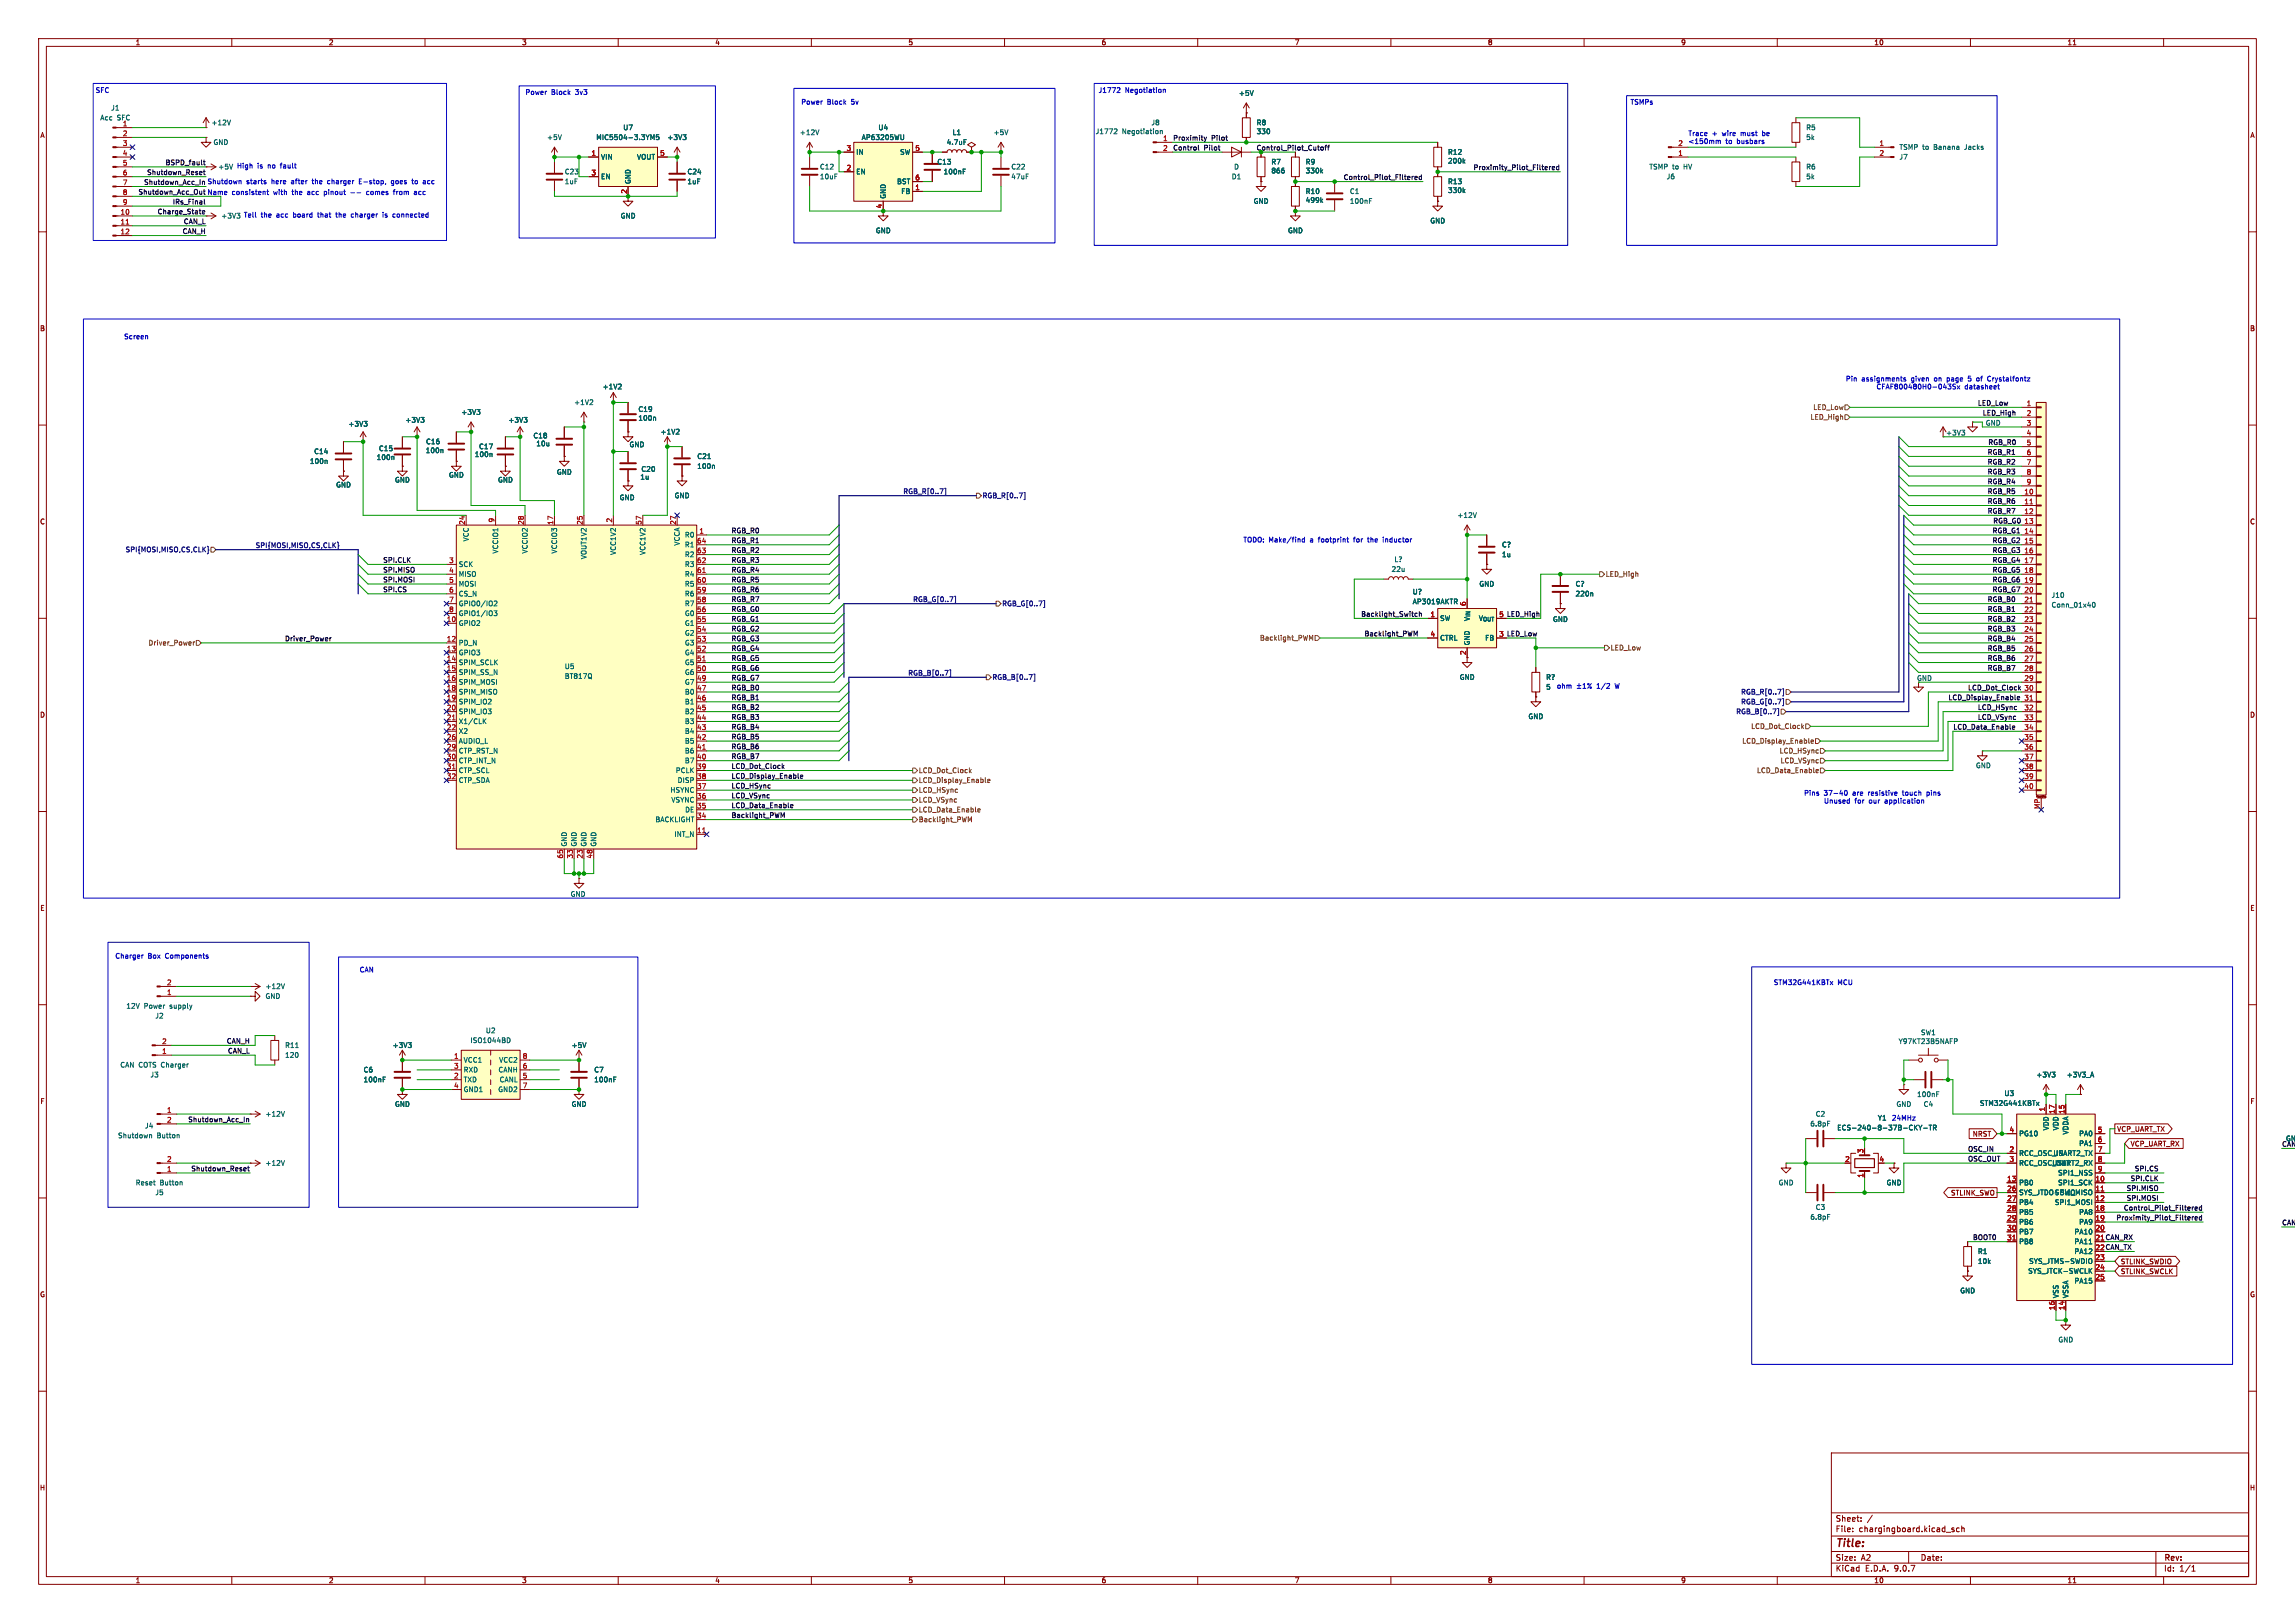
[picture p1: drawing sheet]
<svg xmlns="http://www.w3.org/2000/svg" width="594mm" height="420mm" viewBox="0 0 594 420" stroke-linecap="round" stroke-linejoin="round" font-family="sans-serif">
<defs><g id="words">
<text font-size="2.8" fill="#840000" x="475" y="400.9">Title:</text>
<g font-size="2.1" fill="#840000">
<text x="475" y="394">Sheet:</text>
<text x="475" y="396.7">File:</text>
<text x="481.1" y="396.7">chargingboard.kicad_sch</text>
<text x="475" y="406.9">KiCad</text>
<text x="475" y="404.1">Size:</text>
<text x="481.7" y="404.1">A2</text>
<text x="482.7" y="406.9">E.D.A.</text>
<text x="490.3" y="406.9">9.0.7</text>
<text x="497" y="404.1">Date:</text>
<text x="560" y="404.3">Rev:</text>
<text x="560" y="406.9">Id:</text>
<text x="564.1" y="406.9">1/1</text>
</g>
<g font-size="1.8" fill="#840000">
<text x="35" y="11.9">1</text>
<text x="85" y="11.9">2</text>
<text x="135" y="11.9">3</text>
<text x="185" y="11.9">4</text>
<text x="235" y="11.9">5</text>
<text x="285" y="11.9">6</text>
<text x="335" y="11.9">7</text>
<text x="385" y="11.9">8</text>
<text x="435" y="11.9">9</text>
<text x="485" y="11.9">10</text>
<text x="535" y="11.9">11</text>
<text x="10.3" y="35.9">A</text>
<text x="582.3" y="35.9">A</text>
<text x="228.3" y="54" transform="rotate(-90 228.3 54)">4</text>
<text x="10.3" y="85.9">B</text>
<text x="582.3" y="85.9">B</text>
<text x="10.3" y="135.9">C</text>
<text x="582.3" y="135.9">C</text>
<text x="10.3" y="185.9">D</text>
<text x="582.3" y="185.9">D</text>
<text x="10.3" y="235.9">E</text>
<text x="582.3" y="235.9">E</text>
<text x="10.3" y="285.9">F</text>
<text x="582.3" y="285.9">F</text>
<text x="547.8" y="293.1">VCP_UART_TX</text>
<text x="510.5" y="294.3">NRST</text>
<text x="551.3" y="296.9">VCP_UART_RX</text>
<text x="504.8" y="309.6">STLINK_SWO</text>
<text x="542.2" y="323.6">22 CAN_TX</text>
<text x="548.8" y="329.9">STLINK_SWCLK</text>
<text x="548.8" y="327.3">STLINK_SWDIO</text>
<text x="10.3" y="335.9">G</text>
<text x="582.3" y="335.9">G</text>
<text x="10.2" y="385.9">H</text>
<text x="582.2" y="385.9">H</text>
<text x="35" y="409.9">1</text>
<text x="85" y="409.9">2</text>
<text x="135" y="409.9">3</text>
<text x="185" y="409.9">4</text>
<text x="235" y="409.9">5</text>
<text x="285" y="409.9">6</text>
<text x="335" y="409.9">7</text>
<text x="385" y="409.9">8</text>
<text x="435" y="409.9">9</text>
<text x="485" y="409.9">10</text>
<text x="535" y="409.9">11</text>
</g>
<g font-size="1.8" fill="#0000c2">
<text x="24.6" y="24.2">SFC</text>
<text x="135.9" y="24.7">Power</text>
<text x="142.7" y="24.7">Block</text>
<text x="149.1" y="24.7">3v3</text>
<text x="207.3" y="27.3">Power</text>
<text x="214.1" y="27.3">Block</text>
<text x="220.4" y="27.3">5v</text>
<text x="284.2" y="24.2">J1772</text>
<text x="291.2" y="24.2">Negotiation</text>
<text x="421.9" y="27.3">TSMPs</text>
<text x="436.9" y="35.4">Trace</text>
<text x="443.1" y="35.4">+</text>
<text x="445.9" y="35.4">wire</text>
<text x="450.9" y="35.4">must</text>
<text x="456.6" y="35.4">be</text>
<text x="436.9" y="37.4">&lt;150mm</text>
<text x="446.6" y="37.4">to</text>
<text x="449.7" y="37.4">busbars</text>
<text x="53.6" y="47.9">Shutdown</text>
<text x="61.2" y="43.8">High</text>
<text x="63.8" y="47.9">starts</text>
<text x="66.6" y="43.8">is</text>
<text x="69.4" y="43.8">no</text>
<text x="70.4" y="47.9">here</text>
<text x="72.9" y="43.8">fault</text>
<text x="75.7" y="47.9">after</text>
<text x="81.3" y="47.9">the</text>
<text x="85.5" y="47.9">charger</text>
<text x="93.8" y="47.9">E-stop,</text>
<text x="102.4" y="47.9">goes</text>
<text x="108" y="47.9">to</text>
<text x="111" y="47.9">acc</text>
<text x="53.6" y="50.7">Name</text>
<text x="60" y="50.7">consistent</text>
<text x="70.9" y="50.7">with</text>
<text x="75.9" y="50.7">the</text>
<text x="80" y="50.7">acc</text>
<text x="84.5" y="50.7">pinout</text>
<text x="96" y="50.7">comes</text>
<text x="103.2" y="50.7">from</text>
<text x="108.7" y="50.7">acc</text>
<text x="63" y="56.5">Tell</text>
<text x="67.5" y="56.5">the</text>
<text x="71.7" y="56.5">acc</text>
<text x="76.2" y="56.5">board</text>
<text x="82.7" y="56.5">that</text>
<text x="87.7" y="56.5">the</text>
<text x="91.8" y="56.5">charger</text>
<text x="100.2" y="56.5">is</text>
<text x="103" y="56.5">connected</text>
<text x="32" y="88">Screen</text>
<text x="477.6" y="98.9">Pin</text>
<text x="481.8" y="98.9">assignments</text>
<text x="485.6" y="100.9">CFAF800480H0-043Sx</text>
<text x="494.8" y="98.9">given</text>
<text x="500.9" y="98.9">on</text>
<text x="504.4" y="98.9">page</text>
<text x="508.5" y="100.9">datasheet</text>
<text x="510.1" y="98.9">5</text>
<text x="512.5" y="98.9">of</text>
<text x="515.5" y="98.9">Crystalfontz</text>
<text x="321.7" y="140.6">TODO: Make/find</text>
<text x="339.2" y="140.6">a</text>
<text x="341.5" y="140.6">footprint</text>
<text x="350.9" y="140.6">for</text>
<text x="354.7" y="140.6">the</text>
<text x="358.8" y="140.6">inductor</text>
<text x="402.8" y="178.4">ohm</text>
<text x="413.4" y="178.4">1/2</text>
<text x="418.3" y="178.4">W</text>
<text x="466.8" y="206.1">Pins</text>
<text x="472" y="208.1">Unused</text>
<text x="472.1" y="206.1">37-40</text>
<text x="479.6" y="206.1">are</text>
<text x="480" y="208.1">for</text>
<text x="483.8" y="206.1">resistive</text>
<text x="483.9" y="208.1">our</text>
<text x="488.1" y="208.1">application</text>
<text x="492.9" y="206.1">touch</text>
<text x="499.4" y="206.1">pins</text>
<text x="29.7" y="248.3">Charger</text>
<text x="38.3" y="248.3">Box</text>
<text x="42.9" y="248.3">Components</text>
<text x="93" y="251.8">CAN</text>
<text x="459" y="255.2">STM32G441KBTx</text>
<text x="475.6" y="255.2">MCU</text>
<text x="489.5" y="290.2">24MHz</text>
</g>
<g font-size="1.8" fill="#006464">
<text x="28.7" y="28.8">J1</text>
<text x="320.5" y="25">+5V</text>
<text x="25.8" y="31.3">Acc</text>
<text x="30.3" y="31.3">SFC</text>
<text x="54.6" y="32.6">+12V</text>
<text x="161.2" y="33.9">U7</text>
<text x="206.9" y="35.2">+12V</text>
<text x="227.2" y="33.9">U4</text>
<text x="246.4" y="35.2">L1</text>
<text x="257" y="35.2">+5V</text>
<text x="283.5" y="34.9">J1772</text>
<text x="290.4" y="34.9">Negotiation</text>
<text x="297.9" y="32.6">J8</text>
<text x="325.1" y="32.6">R8</text>
<text x="325.1" y="34.9">330</text>
<text x="467.4" y="33.9">R5</text>
<text x="55.1" y="37.7">GND</text>
<text x="141.5" y="36.4">+5V</text>
<text x="154.2" y="36.4">MIC5504-3.3YM5</text>
<text x="155.4" y="41.5">VIN</text>
<text x="164.8" y="41.5">VOUT</text>
<text x="172.6" y="36.4">+3V3</text>
<text x="221.5" y="40.2">IN</text>
<text x="222.9" y="36.4">AP63205WU</text>
<text x="232.8" y="40.2">SW</text>
<text x="244.9" y="37.7">4.7uF</text>
<text x="374.7" y="40.2">R12</text>
<text x="467.4" y="36.4">5k</text>
<text x="491.5" y="41.5">J7</text>
<text x="491.5" y="39">TSMP to</text>
<text x="500.6" y="39">Banana</text>
<text x="508.8" y="39">Jacks</text>
<text x="56.4" y="44">+5V</text>
<text x="146.1" y="47.9">1uF</text>
<text x="146.1" y="45.3">C23</text>
<text x="155.4" y="46.6">EN</text>
<text x="163.4" y="47.8" transform="rotate(-90 163.4 47.8)">GND</text>
<text x="177.8" y="47.9">1uF</text>
<text x="177.8" y="45.3">C24</text>
<text x="212.1" y="44">C12</text>
<text x="212.1" y="46.6">10uF</text>
<text x="221.5" y="45.3">EN</text>
<text x="232.1" y="47.9">BST</text>
<text x="242.5" y="42.8">C13</text>
<text x="244.1" y="45.3">100nF</text>
<text x="261.6" y="44">C22</text>
<text x="261.6" y="46.6">47uF</text>
<text x="318.7" y="46.6">D1</text>
<text x="319.3" y="44">D</text>
<text x="328.9" y="42.8">R7</text>
<text x="328.9" y="45.1">866</text>
<text x="337.8" y="42.8">R9</text>
<text x="337.8" y="45.1">330k</text>
<text x="374.7" y="47.9">R13</text>
<text x="374.7" y="42.5">200k</text>
<text x="426.8" y="44">TSMP to</text>
<text x="431.2" y="46.6">J6</text>
<text x="435.9" y="44">HV</text>
<text x="467.4" y="44">R6</text>
<text x="467.4" y="46.6">5k</text>
<text x="229.5" y="51.6" transform="rotate(-90 229.5 51.6)">GND</text>
<text x="233.2" y="50.4">FB</text>
<text x="324.4" y="52.9">GND</text>
<text x="337.8" y="50.4">R10</text>
<text x="337.8" y="52.7">499k</text>
<text x="349.3" y="50.4">C1</text>
<text x="349.3" y="52.9">100nF</text>
<text x="374.7" y="50.1">330k</text>
<text x="57.2" y="56.7">+3V3</text>
<text x="160.5" y="56.7">GND</text>
<text x="370.1" y="58">GND</text>
<text x="226.6" y="60.6">GND</text>
<text x="333.2" y="60.6">GND</text>
<text x="155.9" y="100.9">+1V2</text>
<text x="119.3" y="107.5">+3V3</text>
<text x="148.5" y="105">+1V2</text>
<text x="165.1" y="106.8">C19</text>
<text x="90.1" y="110.6">+3V3</text>
<text x="104.8" y="109.6">+3V3</text>
<text x="131.5" y="109.6">+3V3</text>
<text x="137.9" y="113.6">C18</text>
<text x="165.1" y="109.1">100n</text>
<text x="170.8" y="112.6">+1V2</text>
<text x="503.6" y="112.9">+3V3</text>
<text x="513.8" y="110.3">GND</text>
<text x="81.2" y="117.7">C14</text>
<text x="97.4" y="119.2">100n</text>
<text x="98" y="116.9">C15</text>
<text x="110.1" y="117.4">100n</text>
<text x="110.1" y="115.2">C16</text>
<text x="122.8" y="118.5">100n</text>
<text x="123.9" y="116.4">C17</text>
<text x="138.7" y="115.7">10u</text>
<text x="162.8" y="115.9">GND</text>
<text x="180.3" y="119">C21</text>
<text x="80.1" y="120.2">100n</text>
<text x="102.1" y="125.1">GND</text>
<text x="116.1" y="123.8">GND</text>
<text x="128.8" y="125.1">GND</text>
<text x="144" y="123">GND</text>
<text x="165.6" y="124.3">1u</text>
<text x="165.9" y="122.3">C20</text>
<text x="180.3" y="121.5">100n</text>
<text x="86.9" y="126.3">GND</text>
<text x="160.3" y="129.6">GND</text>
<text x="174.5" y="129.1">GND</text>
<text x="377.1" y="134.2">+12V</text>
<text x="121.5" y="140.2" transform="rotate(-90 121.5 140.2)">VCC</text>
<text x="129.1" y="143.4" transform="rotate(-90 129.1 143.4)">VCCIO1</text>
<text x="136.8" y="143.4" transform="rotate(-90 136.8 143.4)">VCCIO2</text>
<text x="144.4" y="143.4" transform="rotate(-90 144.4 143.4)">VCCIO3</text>
<text x="159.6" y="143.7" transform="rotate(-90 159.6 143.7)">VCC1V2</text>
<text x="167.2" y="143.7" transform="rotate(-90 167.2 143.7)">VCC1V2</text>
<text x="176.1" y="141.3" transform="rotate(-90 176.1 141.3)">VCCA</text>
<text x="177.1" y="139.3">R0</text>
<text x="177.1" y="141.8">R1</text>
<text x="388.6" y="141.8">C?</text>
<text x="118.6" y="146.9">SCK</text>
<text x="118.6" y="149.5">MISO</text>
<text x="152" y="144.8" transform="rotate(-90 152 144.8)">VOUT1V2</text>
<text x="177.1" y="144.4">R2</text>
<text x="177.1" y="146.9">R3</text>
<text x="177.1" y="149.5">R4</text>
<text x="360.1" y="148.2">22u</text>
<text x="360.8" y="145.6">L?</text>
<text x="388.6" y="144.4">1u</text>
<text x="118.6" y="152">MOSI</text>
<text x="118.6" y="154.5">CS_N</text>
<text x="177.1" y="152">R5</text>
<text x="177.1" y="154.5">R6</text>
<text x="365.5" y="154">U?</text>
<text x="382.8" y="152">GND</text>
<text x="407.7" y="154.5">220n</text>
<text x="407.7" y="152">C?</text>
<text x="530.9" y="154.9">J10</text>
<text x="118.6" y="157.1">GPIO0/IO2</text>
<text x="118.6" y="159.6">GPIO1/IO3</text>
<text x="177.1" y="157.1">R7</text>
<text x="177.1" y="159.6">G0</text>
<text x="365.5" y="156.6">AP3019AKTR</text>
<text x="372.6" y="160.9">SW</text>
<text x="380.6" y="160.9" transform="rotate(-90 380.6 160.9)">V_{IN}</text>
<text x="382.6" y="160.9">V_{OUT}</text>
<text x="401.8" y="161.1">GND</text>
<text x="530.9" y="157.4">Conn_01x40</text>
<text x="118.6" y="162.2">GPIO2</text>
<text x="118.6" y="167.2">PD_N</text>
<text x="177.1" y="162.2">G1</text>
<text x="177.1" y="164.7">G2</text>
<text x="177.1" y="167.2">G3</text>
<text x="372.6" y="166">CTRL</text>
<text x="380.6" y="167.1" transform="rotate(-90 380.6 167.1)">GND</text>
<text x="384.3" y="166">FB</text>
<text x="118.6" y="169.8">GPIO3</text>
<text x="118.6" y="172.3">SPIM_SCLK</text>
<text x="146.1" y="173.3">U5</text>
<text x="177.1" y="169.8">G4</text>
<text x="177.1" y="172.3">G5</text>
<text x="118.6" y="174.9">SPIM_SS_N</text>
<text x="118.6" y="177.4">SPIM_MOSI</text>
<text x="118.6" y="179.9">SPIM_MISO</text>
<text x="146.1" y="175.9">BT817Q</text>
<text x="177.1" y="174.9">G6</text>
<text x="177.1" y="177.4">G7</text>
<text x="177.1" y="179.9">B0</text>
<text x="377.7" y="176.1">GND</text>
<text x="400.1" y="178.7">5</text>
<text x="400.1" y="176.1">R?</text>
<text x="496.1" y="176.4">GND</text>
<text x="118.6" y="182.5">SPIM_IO2</text>
<text x="118.6" y="185">SPIM_IO3</text>
<text x="177.1" y="182.5">B1</text>
<text x="177.1" y="185">B2</text>
<text x="118.6" y="187.6">X1/CLK</text>
<text x="118.6" y="190.1">X2</text>
<text x="177.1" y="187.6">B3</text>
<text x="177.1" y="190.1">B4</text>
<text x="395.5" y="186.3">GND</text>
<text x="118.6" y="192.6">AUDIO_L</text>
<text x="118.6" y="195.2">CTP_RST_N</text>
<text x="118.6" y="197.7">CTP_INT_N</text>
<text x="177.1" y="192.6">B5</text>
<text x="177.1" y="195.2">B6</text>
<text x="177.1" y="197.7">B7</text>
<text x="118.6" y="200.3">CTP_SCL</text>
<text x="118.6" y="202.8">CTP_SDA</text>
<text x="174.8" y="200.3">PCLK</text>
<text x="175.3" y="202.8">DISP</text>
<text x="511.3" y="199">GND</text>
<text x="173.4" y="205.3">HSYNC</text>
<text x="173.6" y="207.9">VSYNC</text>
<text x="169.5" y="213">BACKLIGHT</text>
<text x="177.2" y="210.4">DE</text>
<text x="146.9" y="219.2" transform="rotate(-90 146.9 219.2)">GND</text>
<text x="149.5" y="219.2" transform="rotate(-90 149.5 219.2)">GND</text>
<text x="152" y="219.2" transform="rotate(-90 152 219.2)">GND</text>
<text x="154.5" y="219.2" transform="rotate(-90 154.5 219.2)">GND</text>
<text x="174.4" y="216.8">INT_N</text>
<text x="147.6" y="232.3">GND</text>
<text x="68.6" y="256.1">+12V</text>
<text x="32.6" y="261.2">12V</text>
<text x="37.3" y="261.2">Power</text>
<text x="40.1" y="263.8">J2</text>
<text x="44.1" y="261.2">supply</text>
<text x="68.6" y="258.7">GND</text>
<text x="125.6" y="267.6">U2</text>
<text x="497.1" y="268.1">SW1</text>
<text x="73.7" y="273.9">120</text>
<text x="73.7" y="271.4">R11</text>
<text x="101.5" y="271.4">+3V3</text>
<text x="119.9" y="275.2">VCC1</text>
<text x="121.6" y="270.1">ISO1044BD</text>
<text x="129.1" y="275.2">VCC2</text>
<text x="147.8" y="271.4">+5V</text>
<text x="491.3" y="270.4">Y97KT23B5NAFP</text>
<text x="31" y="276.5">CAN COTS Charger</text>
<text x="38.8" y="279">J3</text>
<text x="94" y="277.7">C6</text>
<text x="94" y="280.3">100nF</text>
<text x="119.9" y="277.7">RXD</text>
<text x="119.9" y="280.3">TXD</text>
<text x="128.9" y="277.7">CANH</text>
<text x="129.2" y="280.3">CANL</text>
<text x="153.7" y="277.7">C7</text>
<text x="153.7" y="280.3">100nF</text>
<text x="526.9" y="279">+3V3</text>
<text x="534.8" y="279">+3V3_A</text>
<text x="102.1" y="286.6">GND</text>
<text x="119.9" y="282.8">GND1</text>
<text x="128.8" y="282.8">GND2</text>
<text x="147.8" y="286.6">GND</text>
<text x="490.7" y="286.6">GND</text>
<text x="496.1" y="284.1">100nF</text>
<text x="497.8" y="286.6">C4</text>
<text x="512.3" y="286.4">STM32G441KBTx</text>
<text x="518.7" y="283.8">U3</text>
<text x="37.4" y="292.2">J4</text>
<text x="68.6" y="289.2">+12V</text>
<text x="468.4" y="291.7">6.8pF</text>
<text x="469.8" y="289.2">C2</text>
<text x="475.4" y="292.7">ECS-240-8-37B-CKY-TR</text>
<text x="485.9" y="290.2">Y1</text>
<text x="530.5" y="292.6" transform="rotate(-90 530.5 292.6)">VDD</text>
<text x="533" y="292.6" transform="rotate(-90 533 292.6)">VDD</text>
<text x="535.5" y="293.7" transform="rotate(-90 535.5 293.7)">VDDA</text>
<text x="30.4" y="294.7">Shutdown</text>
<text x="40.6" y="294.7">Button</text>
<text x="522.5" y="294.2">PG10</text>
<text x="522.5" y="299.3">RCC_OSC_IN</text>
<text x="531.4" y="299.3">USART2_TX</text>
<text x="538" y="294.2">PA0</text>
<text x="538" y="296.8">PA1</text>
<text x="591.5" y="295.5">GND</text>
<text x="68.6" y="301.9">+12V</text>
<text x="522.5" y="301.9">RCC_OSC_OUT</text>
<text x="531.1" y="301.9">USART2_RX</text>
<text x="532.6" y="304.4">SPI1_NSS</text>
<text x="35" y="306.9">Reset</text>
<text x="40.1" y="309.5">J5</text>
<text x="41.4" y="306.9">Button</text>
<text x="460.2" y="306.9">GND</text>
<text x="488.2" y="306.9">GND</text>
<text x="522.5" y="306.9">PB0</text>
<text x="522.5" y="309.5">SYS_JTDO-SWO</text>
<text x="531.7" y="309.5">SPI1_MISO</text>
<text x="532.6" y="306.9">SPI1_SCK</text>
<text x="468.4" y="315.8">6.8pF</text>
<text x="469.8" y="313.3">C3</text>
<text x="522.5" y="312">PB4</text>
<text x="522.5" y="314.6">PB5</text>
<text x="522.5" y="317.1">PB6</text>
<text x="531.7" y="312">SPI1_MOSI</text>
<text x="538" y="314.6">PA8</text>
<text x="538" y="317.1">PA9</text>
<text x="522.5" y="319.6">PB7</text>
<text x="522.5" y="322.2">PB8</text>
<text x="536.8" y="319.6">PA10</text>
<text x="536.8" y="322.2">PA11</text>
<text x="511.8" y="324.7">R1</text>
<text x="511.8" y="327.3">10k</text>
<text x="524.8" y="329.8">SYS_JTCK-SWCLK</text>
<text x="525.1" y="327.3">SYS_JTMS-SWDIO</text>
<text x="536.8" y="324.7">PA12</text>
<text x="507.2" y="334.9">GND</text>
<text x="536.8" y="332.3">PA15</text>
<text x="533" y="336" transform="rotate(-90 533 336)">VSS</text>
<text x="535.5" y="336" transform="rotate(-90 535.5 336)">VSSA</text>
<text x="532.6" y="347.6">GND</text>
</g>
<g font-size="1.8" fill="#a90000">
<text x="31.7" y="32.8">1</text>
<text x="31.7" y="35.3">2</text>
<text x="31.7" y="37.8">3</text>
<text x="31.7" y="40.4">4</text>
<text x="153" y="40.4">1</text>
<text x="170.7" y="40.4">5</text>
<text x="219" y="39.1">3</text>
<text x="236.8" y="39.1">5</text>
<text x="300.9" y="36.6">1</text>
<text x="300.9" y="39.1">2</text>
<text x="434.3" y="40.4">1</text>
<text x="434.3" y="37.8">2</text>
<text x="486.3" y="37.8">1</text>
<text x="486.3" y="40.4">2</text>
<text x="31.7" y="42.9">5</text>
<text x="31.7" y="45.5">6</text>
<text x="153" y="45.5">3</text>
<text x="219" y="44.2">2</text>
<text x="236.8" y="46.7">6</text>
<text x="31.7" y="48">7</text>
<text x="31.7" y="50.5">8</text>
<text x="31.7" y="53.1">9</text>
<text x="162.3" y="50.2" transform="rotate(-90 162.3 50.2)">2</text>
<text x="236.8" y="49.3">1</text>
<text x="31.1" y="55.6">10</text>
<text x="31.1" y="58.2">11</text>
<text x="31.1" y="60.7">12</text>
<text x="524.4" y="105.2">1</text>
<text x="524.4" y="107.7">2</text>
<text x="524.4" y="110.2">3</text>
<text x="524.4" y="112.8">4</text>
<text x="524.4" y="115.3">5</text>
<text x="524.4" y="117.9">6</text>
<text x="524.4" y="120.4">7</text>
<text x="524.4" y="122.9">8</text>
<text x="524.4" y="125.5">9</text>
<text x="523.8" y="128">10</text>
<text x="523.8" y="130.6">11</text>
<text x="120.4" y="135.9" transform="rotate(-90 120.4 135.9)">24</text>
<text x="128" y="135.3" transform="rotate(-90 128 135.3)">9</text>
<text x="135.6" y="135.9" transform="rotate(-90 135.6 135.9)">28</text>
<text x="143.3" y="135.9" transform="rotate(-90 143.3 135.9)">17</text>
<text x="150.9" y="135.9" transform="rotate(-90 150.9 135.9)">25</text>
<text x="158.5" y="135.3" transform="rotate(-90 158.5 135.3)">2</text>
<text x="166.1" y="135.9" transform="rotate(-90 166.1 135.9)">57</text>
<text x="175" y="135.9" transform="rotate(-90 175 135.9)">27</text>
<text x="523.8" y="133.1">12</text>
<text x="523.8" y="135.6">13</text>
<text x="180.3" y="140.7">64</text>
<text x="180.3" y="143.3">63</text>
<text x="180.9" y="138.2">1</text>
<text x="523.8" y="138.2">14</text>
<text x="523.8" y="140.7">15</text>
<text x="523.8" y="143.3">16</text>
<text x="116.1" y="145.8">3</text>
<text x="116.1" y="148.3">4</text>
<text x="180.3" y="145.8">62</text>
<text x="180.3" y="148.3">61</text>
<text x="523.8" y="145.8">17</text>
<text x="523.8" y="148.3">18</text>
<text x="116.1" y="150.9">5</text>
<text x="116.1" y="153.4">6</text>
<text x="116.1" y="156">7</text>
<text x="180.3" y="150.9">60</text>
<text x="180.3" y="153.4">59</text>
<text x="180.3" y="156">58</text>
<text x="523.8" y="150.9">19</text>
<text x="523.8" y="153.4">20</text>
<text x="523.8" y="156">21</text>
<text x="115.5" y="161">10</text>
<text x="116.1" y="158.5">8</text>
<text x="180.3" y="158.5">56</text>
<text x="180.3" y="161">55</text>
<text x="370.1" y="159.8">1</text>
<text x="379.5" y="156.9" transform="rotate(-90 379.5 156.9)">6</text>
<text x="387.9" y="159.8">5</text>
<text x="523.8" y="158.5">22</text>
<text x="523.8" y="161">23</text>
<text x="115.5" y="166.1">12</text>
<text x="180.3" y="163.6">54</text>
<text x="180.3" y="166.1">53</text>
<text x="370.1" y="164.8">4</text>
<text x="387.9" y="164.8">3</text>
<text x="523.8" y="163.6">24</text>
<text x="523.8" y="166.1">25</text>
<text x="115.5" y="168.7">13</text>
<text x="115.5" y="171.2">14</text>
<text x="115.5" y="173.7">15</text>
<text x="180.3" y="168.7">52</text>
<text x="180.3" y="171.2">51</text>
<text x="180.3" y="173.7">50</text>
<text x="379.5" y="169.6" transform="rotate(-90 379.5 169.6)">2</text>
<text x="523.8" y="168.7">26</text>
<text x="523.8" y="171.2">27</text>
<text x="523.8" y="173.7">28</text>
<text x="115.5" y="176.3">16</text>
<text x="115.5" y="178.8">18</text>
<text x="180.3" y="176.3">49</text>
<text x="180.3" y="178.8">47</text>
<text x="523.8" y="176.3">29</text>
<text x="523.8" y="178.8">30</text>
<text x="115.5" y="181.4">19</text>
<text x="115.5" y="183.9">20</text>
<text x="180.3" y="181.4">46</text>
<text x="180.3" y="183.9">45</text>
<text x="523.8" y="181.4">31</text>
<text x="523.8" y="183.9">32</text>
<text x="115.5" y="186.4">21</text>
<text x="115.5" y="189">22</text>
<text x="115.5" y="191.5">26</text>
<text x="180.3" y="186.4">44</text>
<text x="180.3" y="189">43</text>
<text x="180.3" y="191.5">42</text>
<text x="523.8" y="186.4">33</text>
<text x="523.8" y="189">34</text>
<text x="523.8" y="191.5">35</text>
<text x="115.5" y="194.1">29</text>
<text x="115.5" y="196.6">30</text>
<text x="180.3" y="194.1">41</text>
<text x="180.3" y="196.6">40</text>
<text x="523.8" y="194.1">36</text>
<text x="523.8" y="196.6">37</text>
<text x="115.5" y="199.1">31</text>
<text x="115.5" y="201.7">32</text>
<text x="180.3" y="199.1">39</text>
<text x="180.3" y="201.7">38</text>
<text x="523.8" y="199.1">38</text>
<text x="523.8" y="201.7">39</text>
<text x="180.3" y="204.2">37</text>
<text x="180.3" y="206.8">36</text>
<text x="180.3" y="209.3">35</text>
<text x="523.8" y="204.2">40</text>
<text x="528.1" y="209.5" transform="rotate(-90 528.1 209.5)">MP</text>
<text x="180.3" y="211.8">34</text>
<text x="180.3" y="215.6">11</text>
<text x="145.8" y="222.3" transform="rotate(-90 145.8 222.3)">65</text>
<text x="148.3" y="222.3" transform="rotate(-90 148.3 222.3)">33</text>
<text x="150.9" y="222.3" transform="rotate(-90 150.9 222.3)">23</text>
<text x="153.4" y="222.3" transform="rotate(-90 153.4 222.3)">48</text>
<text x="43.1" y="257.6">1</text>
<text x="43.1" y="255">2</text>
<text x="41.8" y="272.8">1</text>
<text x="41.8" y="270.3">2</text>
<text x="117.4" y="274.1">1</text>
<text x="135.2" y="274.1">8</text>
<text x="117.4" y="276.6">3</text>
<text x="117.4" y="279.1">2</text>
<text x="117.4" y="281.7">4</text>
<text x="135.2" y="276.6">6</text>
<text x="135.2" y="279.1">5</text>
<text x="135.2" y="281.7">7</text>
<text x="529.3" y="287.7" transform="rotate(-90 529.3 287.7)">1</text>
<text x="43.1" y="288">1</text>
<text x="43.1" y="290.6">2</text>
<text x="520" y="293.1">4</text>
<text x="531.9" y="288.3" transform="rotate(-90 531.9 288.3)">17</text>
<text x="534.4" y="288.3" transform="rotate(-90 534.4 288.3)">15</text>
<text x="542.9" y="293.1">5</text>
<text x="482.3" y="298.5" transform="rotate(-90 482.3 298.5)">3</text>
<text x="520" y="298.2">2</text>
<text x="542.9" y="295.7">6</text>
<text x="542.9" y="298.2">7</text>
<text x="43.1" y="303.3">1</text>
<text x="43.1" y="300.7">2</text>
<text x="477.4" y="300.7">2</text>
<text x="482.3" y="304.9" transform="rotate(-90 482.3 304.9)">1</text>
<text x="486.3" y="300.7">4</text>
<text x="519.4" y="305.8">13</text>
<text x="520" y="300.7">3</text>
<text x="542.2" y="305.8">10</text>
<text x="542.9" y="300.7">8</text>
<text x="542.9" y="303.3">9</text>
<text x="519.4" y="308.4">26</text>
<text x="519.4" y="310.9">27</text>
<text x="542.2" y="308.4">11</text>
<text x="542.2" y="310.9">12</text>
<text x="519.4" y="313.4">28</text>
<text x="519.4" y="316">29</text>
<text x="542.2" y="313.4">18</text>
<text x="542.2" y="316">19</text>
<text x="519.4" y="318.5">30</text>
<text x="519.4" y="321.1">31</text>
<text x="542.2" y="318.5">20</text>
<text x="542.2" y="321.1">21 CAN_RX</text>
<text x="542.2" y="321.1">21</text>
<text x="542.2" y="323.6">22</text>
<text x="542.2" y="326.1">23</text>
<text x="542.2" y="328.7">24</text>
<text x="542.2" y="331.2">25</text>
<text x="531.9" y="339.1" transform="rotate(-90 531.9 339.1)">16</text>
<text x="534.4" y="339.1" transform="rotate(-90 534.4 339.1)">14</text>
</g>
<g font-size="1.8" fill="#0f0f0f">
<text x="303.5" y="36.5">Proximity</text>
<text x="303.5" y="39">Control</text>
<text x="311.6" y="39">Pilot</text>
<text x="313.5" y="36.5">Pilot</text>
<text x="37.2" y="47.9">Shutdown_Acc_In</text>
<text x="38" y="45.4">Shutdown_Reset</text>
<text x="42.7" y="42.8">BSPD_fault</text>
<text x="347.7" y="46.6">Control_Pilot_Filtered</text>
<text x="381.3" y="44.1">Proximity_Pilot_Filtered</text>
<text x="35.7" y="50.5">Shutdown_Acc_Out</text>
<text x="44.6" y="53">IRs_Final</text>
<text x="40.7" y="55.5">Charge_State</text>
<text x="47.5" y="58.1">CAN_L</text>
<text x="47.1" y="60.6">CAN_H</text>
<text x="511.8" y="105.1">LED_Low</text>
<text x="513.1" y="107.6">LED_High</text>
<text x="514.3" y="117.8">RGB_R1</text>
<text x="514.5" y="115.2">RGB_R0</text>
<text x="514.3" y="125.4">RGB_R4</text>
<text x="514.3" y="122.8">RGB_R3</text>
<text x="514.3" y="120.3">RGB_R2</text>
<text x="514.3" y="130.5">RGB_R6</text>
<text x="514.3" y="127.9">RGB_R5</text>
<text x="514.3" y="133">RGB_R7</text>
<text x="515.8" y="135.5">RGB_G0</text>
<text x="189.2" y="143.2">RGB_R2</text>
<text x="189.2" y="140.6">RGB_R1</text>
<text x="189.2" y="138.1">RGB_R0</text>
<text x="515.6" y="143.2">RGB_G3</text>
<text x="515.6" y="140.6">RGB_G2</text>
<text x="515.6" y="138.1">RGB_G1</text>
<text x="99.1" y="148.2">SPI.MISO</text>
<text x="99.1" y="145.7">SPI.CLK</text>
<text x="189.2" y="145.7">RGB_R3</text>
<text x="189.2" y="148.2">RGB_R4</text>
<text x="515.6" y="148.2">RGB_G5</text>
<text x="515.6" y="145.7">RGB_G4</text>
<text x="99.1" y="153.3">SPI.CS</text>
<text x="99.1" y="150.8">SPI.MOSI</text>
<text x="189.2" y="155.9">RGB_R7</text>
<text x="189.2" y="150.8">RGB_R5</text>
<text x="189.2" y="153.3">RGB_R6</text>
<text x="514.3" y="155.9">RGB_B0</text>
<text x="515.6" y="150.8">RGB_G6</text>
<text x="515.6" y="153.3">RGB_G7</text>
<text x="189.2" y="160.9">RGB_G1</text>
<text x="189.2" y="158.4">RGB_G0</text>
<text x="352.2" y="159.7">Backlight_Switch</text>
<text x="387.9" y="159.8">5 LED_High</text>
<text x="514.3" y="158.4">RGB_B1</text>
<text x="514.3" y="160.9">RGB_B2</text>
<text x="73.7" y="166">Driver_Power</text>
<text x="189.2" y="166">RGB_G3</text>
<text x="189.2" y="163.5">RGB_G2</text>
<text x="353.1" y="164.8">Backlight_PWM</text>
<text x="387.9" y="164.8">3 LED_Low</text>
<text x="514.3" y="163.5">RGB_B3</text>
<text x="514.3" y="166">RGB_B4</text>
<text x="189.2" y="171.1">RGB_G5</text>
<text x="189.2" y="173.6">RGB_G6</text>
<text x="189.2" y="168.6">RGB_G4</text>
<text x="514.3" y="173.6">RGB_B7</text>
<text x="514.3" y="171.1">RGB_B6</text>
<text x="514.3" y="168.6">RGB_B5</text>
<text x="189.2" y="178.7">RGB_B0</text>
<text x="189.2" y="176.2">RGB_G7</text>
<text x="509.3" y="178.7">LCD_Dot_Clock</text>
<text x="189.2" y="183.8">RGB_B2</text>
<text x="189.2" y="181.3">RGB_B1</text>
<text x="504.2" y="181.3">LCD_Display_Enable</text>
<text x="511.8" y="183.8">LCD_HSync</text>
<text x="189.2" y="188.9">RGB_B4</text>
<text x="189.2" y="191.4">RGB_B5</text>
<text x="189.2" y="186.3">RGB_B3</text>
<text x="505.5" y="188.9">LCD_Data_Enable</text>
<text x="511.8" y="186.3">LCD_VSync</text>
<text x="189.2" y="196.5">RGB_B7</text>
<text x="189.2" y="194">RGB_B6</text>
<text x="189.2" y="201.6">LCD_Display_Enable</text>
<text x="189.2" y="199">LCD_Dot_Clock</text>
<text x="189.2" y="209.2">LCD_Data_Enable</text>
<text x="189.2" y="204.1">LCD_HSync</text>
<text x="189.2" y="206.7">LCD_VSync</text>
<text x="189.2" y="211.7">Backlight_PWM</text>
<text x="58.6" y="270.2">CAN_H</text>
<text x="58.9" y="272.7">CAN_L</text>
<text x="48.6" y="290.5">Shutdown_Acc_In</text>
<text x="509.3" y="298.1">OSC_IN</text>
<text x="590.5" y="296.8">CAN_</text>
<text x="49.4" y="303.2">Shutdown_Reset</text>
<text x="509.3" y="300.6">OSC_OUT</text>
<text x="551.3" y="305.7">SPI.CLK</text>
<text x="552.4" y="303.2">SPI.CS</text>
<text x="550.3" y="310.8">SPI.MOSI</text>
<text x="550.3" y="308.3">SPI.MISO</text>
<text x="547.7" y="315.9">Proximity_Pilot_Filtered</text>
<text x="549.6" y="313.3">Control_Pilot_Filtered</text>
<text x="590.5" y="317.2">CAN_</text>
<text x="510.5" y="321">BOOT0</text>
</g>
<text font-size="1.8" fill="#009600" x="325.1" y="39">Control_Pilot_Cutoff</text>
<g font-size="1.8" fill="#725600">
<text x="469.2" y="106.3">LED_Low</text>
<text x="468.5" y="108.8">LED_High</text>
<text x="415.5" y="149.5">LED_High</text>
<text x="38.3" y="167.2">Driver_Power</text>
<text x="326" y="166">Backlight_PWM</text>
<text x="416.8" y="168.5">LED_Low</text>
<text x="453.1" y="188.8">LCD_Dot_Clock</text>
<text x="450.8" y="192.6">LCD_Display_Enable</text>
<text x="460.5" y="195.2">LCD_HSync</text>
<text x="460.7" y="197.7">LCD_VSync</text>
<text x="237.7" y="200.3">LCD_Dot_Clock</text>
<text x="237.7" y="202.8">LCD_Display_Enable</text>
<text x="454.6" y="200.3">LCD_Data_Enable</text>
<text x="237.7" y="205.3">LCD_HSync</text>
<text x="237.7" y="207.9">LCD_VSync</text>
<text x="237.7" y="213">Backlight_PWM</text>
<text x="237.7" y="210.4">LCD_Data_Enable</text>
</g>
<g font-size="1.8" fill="#000084">
<text x="233.7" y="127.9">RGB_R[0..7]</text>
<text x="254.2" y="129.1">RGB_R[0..7]</text>
<text x="32.4" y="143.1">SPI{MOSI,MISO,CS,CLK}</text>
<text x="66" y="141.9">SPI{MOSI,MISO,CS,CLK}</text>
<text x="236.2" y="155.9">RGB_G[0..7]</text>
<text x="259.3" y="157.1">RGB_G[0..7]</text>
<text x="234.9" y="174.9">RGB_B[0..7]</text>
<text x="256.7" y="176.1">RGB_B[0..7]</text>
<text x="450.5" y="179.9">RGB_R[0..7]</text>
<text x="449.2" y="185">RGB_B[0..7]</text>
<text x="450.5" y="182.5">RGB_G[0..7]</text>
</g>
<text font-size=".5" fill="#840000" x="526.9" y="206.5">Mounting</text>
</g></defs>
<g fill="none" stroke="#840000" stroke-width=".26">
<path d="M10 10h574v400h-574zM12 12h570v396h-570zM60 10v2M110 10v2M160 10v2M210 10v2M260 10v2M310 10v2M360 10v2M410 10v2M460 10v2M510 10v2"/>
<path d="M536.6 11.6h.7M560 10v2M10 60h2M582 60h2M10 110h2M582 110h2M10 160h2M582 160h2M10 210h2M582 210h2M10 260h2M582 260h2"/>
<path d="M10 310h2M582 310h2M10 360h2M474 376h108v32h-108zM582 360h2M474 397.5h108M474 391.5h108M479.5 396.2v.2M479.5 395.4v.2M481.7 393.5v.2M481.7 392.7v.2M484.6 392.1l-1.3 1.9"/>
<path d="M505.7 395.4h-.3l-.2 .2v.2l.5 .1v.4h-.5M507.1 395.4h-.4l-.3 .3 .1 .6h.6M507.7 395.5l.6-.1 .1 1M507.7 394.9v1.5M60 408v2M110 408v2M160 408v2M210 408v2M260 408v2M310 408v2M360 408v2M410 408v2"/>
<path d="M460 408v2M474 404.5h108M474 401.5h108M494 401.5v3M510 408v2M536.6 409.6h.7M558 401.5v6.5M560 408v2M567.3 406.6h.9M567.3 405.5l.4-.4v1.5"/>
</g>
<path d="M221 36.8h15.2v15.3h-15.2z" fill="#ffffc2"/>
<path d="M218.4 39.4h2.6M221 36.8h15.2v15.3h-15.2zM236.2 39.4h2.6M53.3 43.2h.1M53.3 43.2h2.6M54.6 42.4l1.3 .8M55.9 43.2l-1.3 .7M218.4 44.5h2.6M228.6 52.1v2.5M236.2 47h2.6M236.2 49.5h2.6" fill="none" stroke="#840000" stroke-width=".26"/>
<path d="M233.9 34.9v1l-.5 .2M60.2 42.5l-.4 1.3" fill="none" stroke="#006464" stroke-width=".26"/>
<path d="M119.4 271.8h15.2v12.7h-15.2z" fill="#ffffc2"/>
<g fill="none" stroke="#840000" stroke-width=".26">
<path d="M396.5 174h2v5.1h-2zM397.5 172.7v1.3M397.5 179.1v1.2M116.8 274.3h2.6M116.8 276.9h2.6M116.8 279.4h2.6M119.4 271.8h15.2v12.7h-15.2zM127 271.8v1.3M127 274.3v1.3M127 276.9v1.2M127 279.4v1.3M134.6 274.3h2.6"/>
<path d="M134.6 276.9h2.6M134.6 279.4h2.6M116.8 281.9h2.6M127 281.9v1.3M134.6 281.9h2.6M149.9 281.9v1.3h1.2l-1.2 1.3-1.3-1.3h1.3M149.9 281.9h.1"/>
</g>
<path d="M131.6 268.5a.68 .68 0 0 1 .4 .7 .68 .68 0 0 1-.4 .6" fill="none" stroke="#006464" stroke-width=".26"/>
<path d="M527 104.1h2.6v101.6h-2.6z" fill="#ffffc2"/>
<g fill="none" stroke="#840000" stroke-width=".26">
<path d="M485.1 38.1h4.3M485.1 40.6h4.3M523.2 105.4h3.8M523.2 108h3.8M523.2 110.5h3.8M523.2 113h3.8M523.2 115.6h3.8M523.2 118.1h3.8M527 104.1h2.6v101.6h-2.6zM527 105.3h1.3v.2h-1.3zM527 107.8h1.3v.3h-1.3zM527 110.4h1.3v.2h-1.3z"/>
<path d="M527 112.9h1.3v.3h-1.3zM527 115.4h1.3v.3h-1.3zM527 118h1.3v.2h-1.3zM523.2 120.7h3.8M523.2 123.2h3.8M523.2 125.7h3.8M523.2 128.3h3.8M523.2 130.8h3.8M523.2 133.4h3.8M523.2 135.9h3.8M523.2 138.4h3.8M527 120.5h1.3v.3h-1.3z"/>
<path d="M527 123.1h1.3v.2h-1.3zM527 125.6h1.3v.3h-1.3zM527 128.1h1.3v.3h-1.3zM527 130.7h1.3v.2h-1.3zM527 133.2h1.3v.3h-1.3zM527 135.8h1.3v.2h-1.3zM527 138.3h1.3v.3h-1.3zM523.2 141h3.8M523.2 143.5h3.8M523.2 146.1h3.8M523.2 148.6h3.8M523.2 151.1h3.8"/>
<path d="M523.2 153.7h3.8M523.2 156.2h3.8M523.2 158.8h3.8M527 140.8h1.3v.3h-1.3zM527 143.4h1.3v.2h-1.3zM527 145.9h1.3v.3h-1.3zM527 148.5h1.3v.2h-1.3zM527 151h1.3v.3h-1.3zM527 153.5h1.3v.3h-1.3zM527 156.1h1.3v.2h-1.3zM527 158.6h1.3v.3h-1.3zM523.2 161.3h3.8"/>
<path d="M523.2 163.8h3.8M523.2 166.4h3.8M523.2 168.9h3.8M523.2 171.5h3.8M523.2 174h3.8M523.2 176.5h3.8M523.2 179.1h3.8M527 161.2h1.3v.2h-1.3zM527 163.7h1.3v.3h-1.3zM527 166.2h1.3v.3h-1.3zM527 168.8h1.3v.2h-1.3zM527 171.3h1.3v.3h-1.3z"/>
<path d="M527 173.9h1.3v.2h-1.3zM527 176.4h1.3v.3h-1.3zM527 178.9h1.3v.3h-1.3zM397.5 180.3v1.3h1.3l-1.3 1.3-1.3-1.3h1.3M397.5 180.3h.1M523.2 181.6h3.8M523.2 184.2h3.8M523.2 186.7h3.8M523.2 189.2h3.8M523.2 191.8h3.8M523.2 194.3h3.8M523.2 196.9h3.8"/>
<path d="M523.2 199.4h3.8M527 181.5h1.3v.2h-1.3zM527 184h1.3v.3h-1.3zM527 186.6h1.3v.2h-1.3zM527 189.1h1.3v.3h-1.3zM527 191.6h1.3v.3h-1.3zM527 194.2h1.3v.2h-1.3zM527 196.7h1.3v.3h-1.3zM527 199.3h1.3v.2h-1.3zM523.2 201.9h3.8M523.2 204.5h3.8M527 201.8h1.3v.3h-1.3z"/>
<path d="M527 204.3h1.3v.3h-1.3zM527.1 206.3v-.4l.2 .3 .1-.3v.4M527.3 206.5h2M528.3 206.5v3.1M528.6 205.9v.3M528.8 205.9h.1M529.3 206.4h.1M529.3 206.3h.1M529.4 206.3h.1M529.5 206l-.2 .3M529.5 206v.1M529.5 206.4h-.1"/>
<path d="M529.5 206v.3M529.5 206.3v.1M529.5 206.3h.1M64.8 257.8h1.2v-1.3l1.3 1.3-1.3 1.3v-1.3M64.8 257.8h.1M64.8 255.3h.1M64.8 255.3h2.5M66 254.5l1.3 .8M67.3 255.3l-1.3 .7M40.2 273.1h4.2M40.2 270.5h4.2M70.1 269.2h2v5.1h-2z"/>
<path d="M71.1 268v1.2M71.1 274.3v1.3M104.1 274.3h.1M104.1 271.8v5.3M104.1 279.1v2.8M104.1 271.8l-.7 1.3M104.1 271.8l.8 1.3M41.5 288.3h4.2M41.5 290.8h4.2M64.8 288.3h.1M64.8 288.3h2.5M66 287.5l1.3 .8"/>
<path d="M67.3 288.3l-1.3 .8M41.5 303.5h4.2M41.5 301h4.2M64.8 301h.1M64.8 301h2.5M66 300.2l1.3 .8M67.3 301l-1.3 .8"/>
</g>
<path d="M525.4 130.4h.7M525.4 155.8h.7M525.4 181.2h.7" fill="none" stroke="#a90000" stroke-width=".26"/>
<path d="M541.7 155.9h.2a.62 .62 0 0 1 .4 .6 .62 .62 0 0 1-.6 .6l-.1-.4zM73.7 254.6l-.5 1.2M76.5 271.1h.7M99.2 279.3h.4M99.2 278.7h.6M105.7 269.8h.7l-.4 .5M106.2 270.3l.2 .2-.2 .6M38.8 293.7h.4v.8M46.2 293.6l.2 .2v.7M73.7 287.6l-.5 1.3M47 305.8l.1 .2v.6M73.7 300.3l-.5 1.3" fill="none" stroke="#006464" stroke-width=".26"/>
<path d="M102.1 277.4h4.1M102.1 278.9h4.1" fill="none" stroke="#840000" stroke-width=".51"/>
<g fill="#840000" stroke="#840000" stroke-width=".26">
<path d="M489.4 38h.8v.2h-.8z"/>
<path d="M489.4 40.5h.8v.3h-.8z"/>
<path d="M39.4 272.9h.8v.3h-.8z"/>
<path d="M39.4 270.4h.8v.2h-.8z"/>
<path d="M40.6 288.2h.9v.2h-.9z"/>
<path d="M40.6 290.7h.9v.3h-.9z"/>
<path d="M40.6 303.4h.9v.3h-.9z"/>
<path d="M40.6 300.9h.9v.2h-.9z"/>
</g>
<path d="M118.1 135.9h62.2v83.8h-62.2z" fill="#ffffc2"/>
<g fill="none" stroke="#840000" stroke-width=".26">
<path d="M118.1 135.9h62.2v83.8h-62.2zM120.6 133.4v2.5M128.3 133.4v2.5M135.9 133.4v2.5M143.5 133.4v2.5M151.1 133.4v2.5M158.7 133.4v2.5M166.4 133.4v2.5M175.3 133.4v2.5M180.3 138.4h2.6M115.6 146.1h2.5M115.6 148.6h2.5"/>
<path d="M115.6 151.1h2.5M115.6 153.7h2.5M115.6 156.2h2.5M115.6 158.8h2.5M180.3 146.1h2.6M180.3 148.6h2.6M180.3 151.1h2.6M180.3 153.7h2.6M180.3 156.2h2.6M180.3 158.8h2.6M180.3 141h2.6M180.3 143.5h2.6"/>
<path d="M115.6 161.3h2.5M115.6 166.4h2.5M115.6 168.9h2.5M115.6 171.5h2.5M115.6 174h2.5M115.6 176.5h2.5M115.6 179.1h2.5M180.3 161.3h2.6M180.3 166.4h2.6M180.3 168.9h2.6M180.3 171.5h2.6M180.3 174h2.6"/>
<path d="M180.3 176.5h2.6M180.3 179.1h2.6M180.3 163.8h2.6M115.6 181.6h2.5M115.6 184.2h2.5M115.6 186.7h2.5M115.6 189.2h2.5M115.6 191.8h2.5M115.6 194.3h2.5M115.6 196.9h2.5M115.6 199.4h2.5M180.3 181.6h2.6"/>
<path d="M180.3 184.2h2.6M180.3 186.7h2.6M180.3 189.2h2.6M180.3 191.8h2.6M180.3 194.3h2.6M180.3 196.9h2.6M180.3 199.4h2.6M115.6 201.9h2.5M146 219.7v2.6M148.6 219.7v2.6M151.1 219.7v2.6M153.7 219.7v2.6"/>
<path d="M180.3 201.9h2.6M180.3 204.5h2.6M180.3 207h2.6M180.3 209.6h2.6M180.3 212.1h2.6M180.3 215.9h2.6M467.4 308.6h2.8M472.2 308.6h2.8M508.3 322.6h2v5.1h-2zM509.3 328.9v1.3h-1.3l1.3 1.3 1.2-1.3h-1.2M509.3 328.9h.1M509.3 321.3v1.3"/>
<path d="M509.3 327.7v1.2M534.7 341.6v1.3h1.2l-1.2 1.3-1.3-1.3h1.3M534.7 341.6h.1"/>
</g>
<path d="M127.9 158.1h.7l-.4 .4 .4 .2v.5l-.7 .1M127.9 155.6l.5-.1 .2 .4-.7 .9h.7M125.2 186.5l.6 .8M125.8 186l-.7 .7M473 314.3h.6" fill="none" stroke="#006464" stroke-width=".26"/>
<path d="M181.9 148.2h.7M181.9 171h.7M117.1 186.3h.7M117.1 199h.7M181.9 193.9h.7M181.9 215.5h.7" fill="none" stroke="#a90000" stroke-width=".26"/>
<path d="M470.4 306.6v4M471.9 306.6v4" fill="none" stroke="#840000" stroke-width=".51"/>
<path d="M522 288.3h20.3v48.3h-20.3z" fill="#ffffc2"/>
<g fill="none" stroke="#840000" stroke-width=".26">
<path d="M143.5 38.1l-.8 1.3M143.5 38.1l.8 1.3M143.5 38.1v2.5M175.3 38.1l-.8 1.3M175.3 38.1l.7 1.3M175.3 38.1v2.5M243.8 39.4h1.3l.2-.5 .4-.2 .5 .2 .2 .5 .2-.5 .4-.2 .5 .2 .1 .5 .2-.5 .5-.2 .4 .2 .2 .5 .2-.5 .5-.2 .4 .2 .2 .5h1.3M299.3 39.4h4.2M299.3 36.8h4.2M316.2 39.4h7.6M318.8 38.1l2.5 1.3-2.5 1.2zM321.3 38.1v2.5"/>
<path d="M321.6 30.5h2v5.1h-2zM322.6 29.2h.1M322.6 26.7l-.8 1.2M322.6 26.7l.7 1.2M322.6 26.7v3.8M322.6 35.6v1.2M326.4 39.4v1.2M335.3 39.4v1.2M371.1 38.1h2v5.1h-2zM372.1 36.8v1.3M143.5 40.6h.1M143.5 41.9v2.8"/>
<path d="M143.5 46.7v2.8M175.3 40.6h.1M228.6 54.6v1.3h1.3l-1.3 1.3-1.3-1.3h1.3M325.4 40.6h2v5.1h-2zM326.4 47v1.3h1.3l-1.3 1.2-1.3-1.2h1.3M326.4 47h.1M326.4 45.7v1.3M334.3 40.6h2v5.1h-2zM334.3 48.3h2v5h-2zM335.3 54.6v1.3h1.2l-1.2 1.3-1.3-1.3h1.3M335.3 54.6h.1M335.3 45.7v2.6"/>
<path d="M335.3 53.3v1.3M345.4 47v2.8M345.4 51.8v2.8M371.1 45.7h2v5.1h-2zM372.1 52.1v1.2h1.3l-1.3 1.3-1.3-1.3h1.3M372.1 52.1h.1M372.1 43.2v2.5M372.1 50.8v1.3M88.9 114.3v2.8M88.9 119.1v2.8M104.1 113v2.8M104.1 117.9v2.8"/>
<path d="M118.1 119.4v1.3h1.3l-1.3 1.2-1.3-1.2h1.3M118.1 119.4h.1M118.1 111.8v2.8M118.1 116.6v2.8M121.9 111.8h.1M121.9 109.2l-.7 1.3M121.9 109.2l.8 1.3M121.9 109.2v2.6M130.8 113v2.8M130.8 117.9v2.8M146 118.1v1.3h-1.2l1.2 1.3 1.3-1.3h-1.3M146 118.1h.1"/>
<path d="M146 110.5v2.8M146 115.3v2.8M151.1 109.2h.1M151.1 106.7l-.7 1.3M151.1 106.7l.8 1.3M151.1 106.7v2.5M158.7 104.1h.1M158.7 101.6l.8 1.3M158.7 101.6l-.7 1.3M158.7 101.6v2.5M162.6 111.8v1.2h-1.3l1.3 1.3 1.2-1.3h-1.2M162.6 111.8h.1"/>
<path d="M162.6 104.1v2.8M162.6 109v2.8M162.6 116.8v2.8M172.7 115.6h.1M172.7 113l-.7 1.3M172.7 113l.8 1.3M172.7 113v2.6M176.5 115.6v2.8M502.9 113h.1M502.9 110.5l-.7 1.3M502.9 110.5l.8 1.3M502.9 110.5v2.5"/>
<path d="M510.5 109.2v1.3h1.3l-1.3 1.3-1.2-1.3h1.2M510.5 109.2h.1M88.9 121.9v1.3h1.3l-1.3 1.3-1.3-1.3h1.3M88.9 121.9h.1M104.1 120.7v1.2h1.3l-1.3 1.3-1.2-1.3h1.2M104.1 120.7h.1M162.6 124.5v1.2h-1.3l1.3 1.3 1.2-1.3h-1.2M162.6 124.5h.1M162.6 121.7v2.8M176.5 123.2v1.3h1.3l-1.3 1.2-1.2-1.2h1.2M176.5 123.2h.1M176.5 120.4v2.8"/>
<path d="M379.7 170.2v1.3h1.3l-1.3 1.2-1.2-1.2h1.2M496.6 176.5v1.3h1.2l-1.2 1.3-1.3-1.3h1.3M513.1 194.3v1.3h1.2l-1.2 1.3-1.3-1.3h1.3M513.1 194.3h.1M149.9 227.3v1.3h1.2l-1.2 1.3-1.3-1.3h1.3M149.9 227.3h.1M41.5 257.8h4.2M41.5 255.3h4.2M149.9 274.3h.1M149.9 271.8v5.3M149.9 279.1v2.8M149.9 271.8l-.8 1.3"/>
<path d="M149.9 271.8l.7 1.3M494 274.3h2.6M495.3 279.4h2.8M496.6 273.1h5M499.1 271.3v1.8M500.1 279.4h2.8M501.6 274.3h2.6M104.1 281.9v1.3h1.3l-1.3 1.3-1.2-1.3h1.2M104.1 281.9h.1M467.4 294.6h2.8M472.2 294.6h2.8M492.8 280.7v1.2h1.2l-1.2 1.3-1.3-1.3h1.3"/>
<path d="M492.8 280.7h.1M519.4 293.4h2.6M519.4 298.5h2.6M522 288.3h20.3v48.3h-20.3zM529.6 283.2h.1M529.6 280.7v2.5M529.6 285.8v2.5M529.6 280.7l-.8 1.2M529.6 280.7l.8 1.2M532.1 285.8v2.5M534.7 285.8v2.5M538.5 283.2h.1"/>
<path d="M538.5 280.7l-.8 1.2M538.5 280.7l.7 1.2M538.5 280.7v2.5M542.3 293.4h2.5M542.3 298.5h2.5M542.3 295.9h2.5M462.3 301v1.3h1.2l-1.2 1.2-1.3-1.2h1.3M462.3 301h.1M519.4 301h2.6M519.4 306.1h2.6M519.4 308.6h2.6M519.4 311.2h2.6"/>
<path d="M519.4 313.7h2.6M519.4 316.2h2.6M519.4 318.8h2.6M542.3 301h2.5M542.3 306.1h2.5M542.3 308.6h2.5M542.3 311.2h2.5M542.3 313.7h2.5M542.3 316.2h2.5M542.3 318.8h2.5M542.3 303.5h2.5M519.4 321.3h2.6"/>
<path d="M532.1 336.6v2.5M534.7 336.6v2.5M542.3 326.4h2.5M542.3 328.9h2.5M542.3 331.5h2.5"/>
<circle cx="497.1" cy="274.3" r=".51"/>
<circle cx="501.1" cy="274.3" r=".51"/>
</g>
<path d="M543.8 308.2h.7M520.9 320.9h.8" fill="none" stroke="#a90000" stroke-width=".26"/>
<g fill="none" stroke="#006464" stroke-width=".26">
<path d="M145.3 34.9l-.4 1.2M176.8 34.9h.8l-.5 .5M177.3 35.4l.3 .2-.3 .5M249.5 36.1h.6M288.6 33.3l.4 .1 .1 .3-.8 .9h.8M300.3 33.8v.8M300.3 33.9l.5-.1 .1 .8M324.4 23.4l-.4 1.3M342 44.3l.3 .5M342 51.9l.3 .5M342.3 43.9l-.4 .5M342.3 51.5l-.4 .5"/>
<path d="M354.4 52h.5M354.4 51.4h.6M378.8 49.4l.4 .5M378.8 41.8l.4 .4M379.2 49l-.5 .5M379.2 41.4l-.5 .5M160.6 99.4l.2 .2-.1 .3-.7 .8h.8M84.5 119.1l.2 .2v.7M101.8 118.1l.1 .2v.6M114.5 116.3l.1 .2v.7M123.4 106h.8l-.4 .5M124 106.5l.2 .2-.2 .6"/>
<path d="M127.2 117.3l.1 .2v.7M153.2 103.4l.2 .3v.3l-.8 .7h.8M169.5 107.9l.2 .2v.7M175.5 111.1l.3 .2-.1 .3-.7 .7h.8M183.2 118.7h.7M507.7 111.3h.8l-.4 .5M508.3 111.8l.2 .2-.2 .6M184.7 120.4l.2 .2v.6M151.7 269.8l-.4 1.3M158.9 279.3h.4M158.9 278.7h.6M505.9 268.8h.4l.3 .2-.1 .4-.6 .1"/>
<path d="M531.1 277.4h.8l-.4 .5M531.6 277.9l.3 .3-.3 .5M541.2 278.3h.6M541.5 277.4l.4 1.3M473 290.1h.6M501.3 283.1h.4M501.3 282.5h.6M527.1 285.2l.6 .9M527.7 285.2l-.6 .9M540.7 321.9h.7M540.9 328.8l.5 .7M541.3 325.8l.1 .3-.1 .8"/>
<path d="M541.4 328.2l-.7 .8"/>
</g>
<g fill="none" stroke="#840000" stroke-width=".51">
<path d="M141.5 46.5h4M141.5 45h4M343.4 50h4.1M343.4 51.6h4.1M86.9 117.3h4M86.9 118.9h4M102.1 116.1h4.1M102.1 117.6h4.1M116.1 114.8h4M116.1 116.3h4M128.8 116.1h4M128.8 117.6h4"/>
<path d="M144 113.5h4.1M144 115.1h4.1M160.5 107.2h4.1M160.5 108.7h4.1M160.5 119.9h4.1M174.5 118.6h4.1M160.5 121.4h4.1M174.5 120.1h4.1M147.8 277.4h4.1M147.8 278.9h4.1M498.3 277.4v4M499.9 277.4v4"/>
<path d="M470.4 292.6v4.1M471.9 292.6v4.1"/>
</g>
<g fill="#840000" stroke="#840000" stroke-width=".26">
<path d="M298.4 36.7h.9v.3h-.9z"/>
<path d="M298.4 39.2h.9v.3h-.9z"/>
<path d="M40.6 257.7h.9v.2h-.9z"/>
<path d="M40.6 255.1h.9v.3h-.9z"/>
</g>
<path d="M154.9 38.1h15.3v10.2h-15.3z" fill="#ffffc2"/>
<g fill="none" stroke="#840000" stroke-width=".26">
<path d="M30.1 33h4.2M30.1 35.6h4.2M30.1 38.1h4.2M53.3 33h.1M53.3 35.6v1.2h1.3l-1.3 1.3-1.2-1.3h1.2M53.3 35.6h.1M53.3 30.5l-.7 1.3M53.3 30.5l.8 1.3M53.3 30.5v2.5M154.9 38.1h15.3v10.2h-15.3zM209.5 39.4h.1M209.5 36.8v2.6"/>
<path d="M209.5 36.8l-.7 1.3M209.5 36.8l.8 1.3M241.3 39.4v2.8M251.5 38.1l1-.6-1-.7-1.1 .7 1.1 .6v1.3M251.5 39.4h.1M259.1 39.4h.1M259.1 36.8v2.6M259.1 36.8l-.8 1.3M259.1 36.8l.7 1.3M30.1 40.6h4.2M30.1 45.7h4.2M30.1 55.9h4.2"/>
<path d="M30.1 43.2h4.2M30.1 48.3h4.2M30.1 50.8h4.2M30.1 53.3h4.2M30.1 58.4h4.2M53.3 55.9h.1M53.3 55.9h2.6M54.6 55.1l1.3 .8M55.9 55.9l-1.3 .7M152.4 40.6h2.5M152.4 45.7h2.5M162.6 48.3v3.8h1.2l-1.2 1.2-1.3-1.2h1.3"/>
<path d="M170.2 40.6h2.5M175.3 41.9v2.8M175.3 46.7v2.8M209.5 40.6v2.8M209.5 45.5v2.8M241.3 44.2v2.8M259.1 40.6v2.8M259.1 45.5v2.8M30.1 61h4.2M94 114.3h.1M94 111.8l-.8 1.2M94 111.8l.7 1.2"/>
<path d="M94 111.8v2.5M107.9 113h.1M107.9 110.5l-.7 1.3M107.9 110.5l.8 1.3M107.9 110.5v2.5M134.6 113h.1M134.6 110.5l-.7 1.3M134.6 110.5l.8 1.3M134.6 110.5v2.5M130.8 120.7v1.2h1.3l-1.3 1.3-1.3-1.3h1.3M130.8 120.7h.1M379.7 138.4h.1"/>
<path d="M379.7 135.9l-.7 1.3M379.7 135.9l.8 1.3M379.7 135.9v2.5M384.8 138.4v2.8M358.1 149.9h1.3l.2-.5 .4-.2 .5 .2 .2 .5 .2-.5 .4-.2 .5 .2 .1 .5 .2-.5 .5-.2 .4 .2 .2 .5 .2-.5 .5-.2 .4 .2 .2 .5h1.3M384.8 146.1v1.2h1.3l-1.3 1.3-1.3-1.3h1.3M384.8 146.1h.1M384.8 143.3v2.8M403.9 156.2v1.3h1.2l-1.2 1.3-1.3-1.3h1.3M403.9 156.2h.1M403.9 148.6v2.8M403.9 153.4v2.8"/>
</g>
<g fill="none" stroke="#006464" stroke-width=".26">
<path d="M59.7 31.1l-.4 1.2M168.5 34.9l.4 .9 .4-.9v1.2M170.5 34.9h-.6l-.1 .6 .7-.1v.6h-.7M212 33.6l-.5 1.3M260.9 33.6l-.4 1.3M61.3 55.2h.8l-.4 .5M61.9 55.7l.2 .2-.2 .6M249.3 44.4h.4M249.3 43.8h.6M94.2 109h.8l-.4 .5M94.8 109.5l.2 .3-.2 .5M109 108h.7l-.4 .5"/>
<path d="M109.5 108.5l.2 .2-.2 .6M135.6 108h.8l-.4 .5M136.2 108.5l.2 .2-.2 .6M382.1 132.7l-.4 1.2M412.1 153.4l.2 .2v.6"/>
</g>
<path d="M173.2 46.5h4.1M173.2 45h4.1M207.5 45.2h4.1M207.5 43.7h4.1M239.3 42.4h4M239.3 43.9h4M257 45.2h4.1M257 43.7h4.1M382.8 141.5h4M382.8 143h4M401.8 151.6h4.1M401.8 153.2h4.1" fill="none" stroke="#840000" stroke-width=".51"/>
<g fill="#840000" stroke="#840000" stroke-width=".26">
<path d="M29.2 32.9h.9v.2h-.9z"/>
<path d="M29.2 35.4h.9v.3h-.9z"/>
<path d="M29.2 38h.9v.2h-.9z"/>
<path d="M29.2 40.5h.9v.3h-.9z"/>
<path d="M29.2 43.1h.9v.2h-.9z"/>
<path d="M29.2 45.6h.9v.2h-.9z"/>
<path d="M29.2 48.1h.9v.3h-.9z"/>
<path d="M29.2 50.7h.9v.2h-.9z"/>
<path d="M29.2 53.2h.9v.3h-.9z"/>
<path d="M29.2 55.8h.9v.2h-.9z"/>
<path d="M29.2 58.3h.9v.2h-.9z"/>
<path d="M29.2 60.8h.9v.3h-.9z"/>
</g>
<path d="M32.6 58h.8" fill="none" stroke="#a90000" stroke-width=".26"/>
<path d="M372.1 157.5h15.2v10.1h-15.2z" fill="#ffffc2"/>
<g fill="none" stroke="#840000" stroke-width=".26">
<path d="M218.4 39.4h2.6M236.2 39.4h2.6M241.3 39.4v2.8M243.8 39.4h1.3M250.2 39.4h1.3M251.5 39.4h.1M322.6 29.2h.1M322.6 29.2v1.3M322.6 35.6v1.2M326.4 39.4v1.2M335.3 39.4v1.2M372.1 36.8v1.3"/>
<path d="M432.7 38.1h4.2M463.8 31.8h2v5h-2zM464.8 30.5v1.3M464.8 36.8v1.3M152.4 40.6h2.5M152.4 45.7h2.5M162.6 48.3v2.5M170.2 40.6h2.5M175.3 40.6h.1M175.3 41.9v2.8M175.3 46.7v2.8M218.4 44.5h2.6"/>
<path d="M228.6 52.1v2.5M236.2 47h2.6M236.2 49.5h2.6M241.3 44.2v2.8M326.4 47h.1M326.4 45.7v1.3M335.3 54.6h.1M335.3 45.7v2.6M335.3 53.3v1.3M372.1 52.1h.1M372.1 43.2v2.5M372.1 50.8v1.3"/>
<path d="M432.7 40.6h4.2M463.8 41.9h2v5.1h-2zM464.8 40.6v1.3M464.8 47v1.3M88.9 114.3v2.8M88.9 119.1v2.8M94 114.3h.1M104.1 113v2.8M104.1 117.9v2.8M107.9 113h.1M118.1 119.4h.1M118.1 111.8v2.8"/>
<path d="M118.1 116.6v2.8M121.9 111.8h.1M130.8 113v2.8M130.8 117.9v2.8M134.6 113h.1M146 118.1h.1M146 110.5v2.8M146 115.3v2.8M158.7 104.1h.1M162.6 111.8h.1M162.6 104.1v2.8M162.6 109v2.8"/>
<path d="M162.6 116.8v2.8M172.7 115.6h.1M176.5 115.6v2.8M88.9 121.9h.1M104.1 120.7h.1M130.8 120.7h.1M162.6 124.5h.1M162.6 121.7v2.8M176.5 123.2h.1M176.5 120.4v2.8M384.8 138.4v2.8M372.1 157.5h15.2v10.1h-15.2z"/>
<path d="M379.7 154.9v2.6M384.8 146.1h.1M384.8 143.3v2.8M403.9 156.2h.1M403.9 148.6v2.8M403.9 153.4v2.8M369.6 160h2.5M369.6 165.1h2.5M379.7 167.6v2.6M387.3 165.1h2.6M397.5 172.7v1.3M397.5 179.1v1.2"/>
<path d="M397.5 180.3h.1M104.1 274.3h.1M104.1 274.3v2.8M104.1 279.1v2.8M149.9 274.3h.1M149.9 274.3v2.8M149.9 279.1v2.8M104.1 281.9h.1M149.9 281.9h.1M480.3 298.5h-1.3v5h1.3M484.9 298.5h1.3v5h-1.3M509.7 292.1h6.1l1.1 1.3-1.1 1.2h-6.1z"/>
<path d="M519.4 293.4h2.6M519.4 298.5h2.6M529.6 283.2h.1M529.6 285.8v2.5M532.1 285.8v2.5M534.7 285.8v2.5M538.5 283.2h.1M542.3 293.4h2.5M542.3 298.5h2.5M542.3 295.9h2.5M547.4 290.8h13.7l1.1 1.3-1.1 1.3h-13.7zM551 294.6h14.1v2.6h-14.1l-1.1-1.3z"/>
<path d="M478.8 301h.2M482.6 303v1.8M490.2 301v1.3h1.3l-1.3 1.2-1.3-1.2h1.3M490.2 301h.1M504.2 307.3h12.7v2.6h-12.7l-1.1-1.3zM519.4 301h2.6M519.4 306.1h2.6M519.4 308.6h2.6M519.4 311.2h2.6M519.4 313.7h2.6M519.4 316.2h2.6M519.4 318.8h2.6"/>
<path d="M542.3 301h2.5M542.3 306.1h2.5M542.3 308.6h2.5M542.3 311.2h2.5M542.3 313.7h2.5M542.3 316.2h2.5M542.3 318.8h2.5M542.3 303.5h2.5M509.3 328.9h.1M509.3 321.3v1.3M509.3 327.7v1.2M519.4 321.3h2.6"/>
<path d="M532.1 336.6v2.5M534.7 336.6v2.5M542.3 326.4h2.5M542.3 328.9h2.5M542.3 331.5h2.5M548.5 327.7h14.9v2.5h-14.9l-1.1-1.3zM548.5 325.1h14.6l1.1 1.3-1.1 1.3h-14.6l-1.1-1.3z"/>
</g>
<g fill="none" stroke="#006464" stroke-width=".26">
<path d="M168.5 34.9l.4 .9 .4-.9v1.2M170.5 34.9h-.6l-.1 .6 .7-.1v.6h-.7M176.8 34.9h.8l-.5 .5M177.3 35.4l.3 .2-.3 .5M233.9 34.9v1l-.5 .2M249.5 36.1h.6M324.4 23.4l-.4 1.3M249.3 44.4h.4M249.3 43.8h.6M342 44.3l.3 .5M342 51.9l.3 .5M342.3 43.9l-.4 .5"/>
<path d="M342.3 51.5l-.4 .5M378.8 49.4l.4 .5M378.8 41.8l.4 .4M379.2 49l-.5 .5M379.2 41.4l-.5 .5M160.6 99.4l.2 .2-.1 .3-.7 .8h.8M84.5 119.1l.2 .2v.7M94.2 109h.8l-.4 .5M94.8 109.5l.2 .3-.2 .5M101.8 118.1l.1 .2v.6M109 108h.7l-.4 .5M109.5 108.5l.2 .2-.2 .6"/>
<path d="M114.5 116.3l.1 .2v.7M123.4 106h.8l-.4 .5M124 106.5l.2 .2-.2 .6M127.2 117.3l.1 .2v.7M135.6 108h.8l-.4 .5M136.2 108.5l.2 .2-.2 .6M169.5 107.9l.2 .2v.7M175.5 111.1l.3 .2-.1 .3-.7 .7h.8M183.2 118.7h.7M184.7 120.4l.2 .2v.6M376.7 155.7l.5 .6M377 155.1v.5"/>
<path d="M412.1 153.4l.2 .2v.6M99.2 279.3h.4M99.2 278.7h.6M105.7 269.8h.7l-.4 .5M106.2 270.3l.2 .2-.2 .6M151.7 269.8l-.4 1.3M158.9 279.3h.4M158.9 278.7h.6M531.1 277.4h.8l-.4 .5M531.6 277.9l.3 .3-.3 .5M541.2 278.3h.6M541.5 277.4l.4 1.3"/>
<path d="M495.7 291.7l.5 .7M496.2 291.2l-.7 .7M496.6 291.2l.4 .6M497 291.8v.6M497.5 291.2l-.5 .6M497.9 291.9h.9M499.3 291.2h.7M499.6 291.2v1.2M500.4 291.8h.6l.1-.5-.7-.1v1.2M500.7 291.8l.4 .6M527.1 285.2l.6 .9M527.7 285.2l-.6 .9"/>
<path d="M540.7 321.9h.7M540.9 328.8l.5 .7M541.3 325.8l.1 .3-.1 .8M541.4 328.2l-.7 .8"/>
</g>
<g fill="#840000" stroke="#840000" stroke-width=".26">
<path d="M431.8 40.5h.9v.3h-.9z"/>
<path d="M431.8 38h.9v.2h-.9z"/>
</g>
<path d="M481.3 299h2.6M481.3 303h2.6" fill="none" stroke="#840000" stroke-width=".51"/>
<path d="M480.1 299.8h5v2.3h-5z" fill="none" stroke="#840000" stroke-width=".3"/>
<g fill="none" stroke="#000084" stroke-width=".26">
<path d="M33.7 37.5l1.2 1.2M34.9 37.5l-1.2 1.2M33.7 40l1.2 1.2M34.9 40l-1.2 1.2M174.7 132.7l1.2 1.3M175.9 132.7l-1.2 1.3M244.5 126.4h.3v1.8h-.3M265 127.5h.3v1.8h-.3M53.7 141.4l.2 .1v.7l.2 .1-.2 .2v.6l-.2 .2M87.3 140.3l.2 .2v.6l.2 .1-.2 .2v.6l-.2 .2M115 155.6l1.2 1.2M115 158.1l1.2 1.3"/>
<path d="M116.2 155.6l-1.2 1.2M116.2 158.1l-1.2 1.3M247 154.3h.3v1.8h-.3M270.1 155.4h.3v1.8h-.3M115 170.8l1.2 1.3M115 168.3l1.2 1.2M115 160.7l1.2 1.2M115 173.4l1.2 1.2M115 178.5l1.2 1.2M115 175.9l1.2 1.2M116.2 170.8l-1.2 1.3M116.2 168.3l-1.2 1.2"/>
<path d="M116.2 160.7l-1.2 1.2M116.2 173.4l-1.2 1.2M116.2 178.5l-1.2 1.2M116.2 175.9l-1.2 1.2M244.5 173.5h.9l-.6 1.2M245.8 173.4h.3v1.8h-.3M266.3 174.6h.9l-.6 1.2M267.5 174.4h.3v1.9h-.3M461.3 178.3h.3v1.8h-.3M115 188.6l1.2 1.2M115 186.1l1.2 1.2M115 191.2l1.2 1.2"/>
<path d="M115 196.2l1.2 1.3M115 193.7l1.2 1.2M115 198.8l1.2 1.2M115 181l1.2 1.2M115 183.5l1.2 1.3M116.2 188.6l-1.2 1.2M116.2 186.1l-1.2 1.2M116.2 191.2l-1.2 1.2M116.2 196.2l-1.2 1.3M116.2 193.7l-1.2 1.2M116.2 198.8l-1.2 1.2M116.2 181l-1.2 1.2"/>
<path d="M116.2 183.5l-1.2 1.3M458.8 183.5h.9l-.6 1.2M460.4 183.3v1.9h-.3M461.3 180.8h.3v1.8h-.3M522.6 191.2l1.2 1.2M522.6 198.8l1.2 1.2M522.6 196.2l1.2 1.3M523.8 191.2l-1.2 1.2M523.8 198.8l-1.2 1.2M523.8 196.2l-1.2 1.3M115 201.3l1.2 1.2M116.2 201.3l-1.2 1.2"/>
<path d="M182.3 215.3l1.2 1.2M183.5 215.3l-1.2 1.2M522.6 201.3l1.2 1.2M522.6 203.9l1.2 1.2M523.8 201.3l-1.2 1.2M523.8 203.9l-1.2 1.2M527.7 208.9l1.2 1.3M528.9 208.9l-1.2 1.3"/>
</g>
<g fill="none" stroke="#725600" stroke-width=".26">
<path d="M477.5 107.3h.7l.6 .7-.6 .6h-.7zM477.5 104.8h.7l.6 .6-.6 .6h-.7zM252.7 127.6h.7l.6 .7-.6 .6h-.7zM54.6 141.6h.6l.7 .6-.7 .7h-.6zM257.8 155.6h.6l.7 .6-.7 .6h-.6zM414 148h.7l.6 .6-.6 .6h-.7zM50 166.1v.8M50.4 166.1l-.4 .2M50.8 165.7h.6l.7 .7-.7 .6h-.6zM255.3 174.6h.6l.6 .7-.6 .6h-.6zM338.9 164.4l.4 .9 .5-.9v1.3M340.4 164.5h.6l.6 .6-.6 .6h-.6z"/>
<path d="M415.3 167h.6l.7 .6-.7 .7h-.6zM462.3 178.4h.6l.6 .7-.6 .6h-.6zM236.2 198.8h.7l.6 .6-.6 .6h-.7zM251 199.5l.4 .5M251.4 199.1l-.5 .5M461 183.5h.6l.7 .7-.7 .6h-.6zM462.3 181h.6l.6 .6-.6 .6h-.6zM466.5 188.1l.3 .4M466.8 187.7l-.5 .5M467.4 187.3h.6l.6 .7-.6 .6h-.6zM468.2 192.2l.1 .1M468.8 191.9l.6-.1-.1-.2-.4-.1-.1 .2v.6h.5"/>
<path d="M469.9 191.1h.6l.7 .7-.7 .6h-.6zM470 199.5l.6-.1v-.2l-.4-.1-.2 .2 .1 .6h.5M471.2 196.2h.6l.6 .7-.6 .6h-.6zM471.2 193.7h.6l.6 .6-.6 .6h-.6zM471.2 198.8h.6l.6 .6-.6 .6h-.6zM236.2 203.8h.7l.6 .7-.6 .6h-.7zM236.2 211.5h.7l.6 .6-.6 .6h-.7zM236.2 206.4h.7l.6 .6-.6 .6h-.7zM236.2 208.9h.7l.6 .7-.6 .6h-.7zM236.2 201.3h.7l.6 .6-.6 .7h-.7zM250.6 211.4l.4 .9 .4-.9v1.3M253.1 209.7l.6-.1-.1-.3h-.3l-.2 .2v.6h.5"/>
<path d="M255 202.3l.2 .2M255.6 202.1l.6-.1v-.3h-.4l-.2 .1 .1 .6h.5"/>
</g>
<g fill="none" stroke="#0f0f0f" stroke-width=".26">
<path d="M310.2 37.6v1.1l.1 .2M311.7 35.5l.3 .8M312 36.3l-.3 .4M312.3 35.5l-.3 .8M315.3 38h.5M315.5 38.8l.3 .1M317.2 35.5h.5M317.5 36.3h.2M341.9 38.1h.6l-.1 .7-.5-.1zM342.9 38h.5M343.4 37.6l-.3 .2v1.1M343.6 38h.5"/>
<path d="M344.1 37.6l-.3 .2v1.1M51.8 44.4h.4l.1 .3-.6 .1M52.2 45.1l-.4 .1M52.2 49.4v.9M52.2 50.2l-.4 .1M52.4 46.9v.8M52.4 54.9l.6-.1-.1-.2-.3-.1-.2 .2 .1 .6h.4M52.4 47h.5v.7M52.6 44.4h.5M52.6 41.8h.5M52.6 49.4h.5M52.8 43.9v1.1l.3 .2"/>
<path d="M52.8 41.4v1.1l.3 .2M52.8 49v1.1l.3 .2M52.9 51.6v1l.2 .2M365.5 45.6v.9M365.8 45.6l-.3 .3M366.2 46.1l.6-.2-.1-.2-.3-.1-.2 .2 .1 .6h.4M367.9 45.7l-.4-.1-.2 .3 .1 .5h.5M367.9 45.2v1.3M400.3 43.1l.2 .3-.6 .1M400.4 43.9h-.1M401 43.1v.8M401.4 43.1l-.4 .2"/>
<path d="M401.8 43.5l.6-.1-.1-.2-.4-.1-.1 .2v.6h.5M403.5 43.2l-.4-.1-.2 .2 .1 .6h.5M403.5 42.7v1.2M366.8 158.7h-.4l-.2 .2 .1 .5h.5M367.4 158.8l.4-.1 .1 .8M367.4 158.2v1.3M85.4 165v.9M85.7 165l-.3 .3M366 163.3l.4 .9 .4-.9v1.3M522.6 178.1l.4 .5M523 177.7l-.5 .5M202.6 198.4l.3 .5"/>
<path d="M202.9 198l-.4 .5M520.9 188.3l.6-.1-.1-.3h-.4l-.1 .2v.6h.5M521.5 180.9l.2 .2M522.1 180.7l.6-.1v-.3h-.4l-.2 .1 .1 .6h.5M202.2 210.3l.4 .9 .4-.9v1.3M204.6 208.6l.6-.1v-.2l-.4-.1-.2 .2 .1 .6h.5M206.6 201.2l.1 .2M207.2 201l.6-.1-.1-.3h-.3l-.2 .2v.6h.5M63.8 289.5v.8M63.8 289.6l.5-.1 .1 .8M63.3 302.2h.3l.1 .3-.6 .1M63.6 303h-.3"/>
<path d="M64.1 302.2h.4M64.2 301.7v1.1l.3 .2M566.7 314.9l.2 .3-.6 .1M566.8 315.7h-.1M567.4 312.3v.9M567.4 314.9v.8M567.8 314.9l-.4 .2M567.8 312.3l-.4 .3M568.1 315.3l.6-.1v-.3h-.4l-.2 .2 .1 .6h.5M568.1 312.8l.6-.2v-.2l-.4-.1-.2 .2 .1 .6h.5M569.8 314.9h-.3l-.3 .2 .1 .6h.5M569.8 311.9v1.3"/>
<path d="M569.8 314.4v1.3M569.8 312.4l-.3-.1-.3 .3 .1 .5h.5"/>
</g>
<path d="M491.5 113v66.1h-28M252.7 128.3h-35.5v26.6M492.8 133.4v48.2h-29.3M55.9 142.2h36.8v11.5M257.8 156.2h-39.4v19.1M494 153.7v30.5h-31.7M255.3 175.3h-35.6v21.6" fill="none" stroke="#000084" stroke-width=".3"/>
<g fill="none" stroke="#009600" stroke-width=".26">
<path d="M34.3 33h19M34.3 35.6h19M217.2 39.4v5.1h1.2M218.4 39.4h-8.9v1.2M238.8 39.4h5M251.5 39.4h7.6v1.2M254 39.4v10.1h-15.2M303.5 39.4h12.7M303.5 36.8h68.6M323.8 39.4h11.5M436.9 38.1h27.9M464.8 30.5h16.5v7.6h3.8"/>
<path d="M34.3 50.8h22.8v2.5h-22.8M34.3 55.9h19M34.3 58.4h19M34.3 43.2h19M34.3 45.7h19M34.3 48.3h19M143.5 49.5v1.3h31.8v-1.3M149.9 40.6v5.1h2.5M152.4 40.6h-8.9v1.3M172.7 40.6h2.6v1.3M209.5 48.3v6.3h49.6v-6.3M238.8 47h2.5"/>
<path d="M335.3 47h33M335.3 54.6h10.1M372.1 44.5h31.8M436.9 40.6h27.9M485.1 40.6h-3.8v7.7h-16.5M34.3 61h19M88.9 114.3h5.1v19.1h26.6M104.1 113h3.8v19.1h20.4v1.3M118.1 111.8h3.8v19h14v2.6M130.8 113h3.8v16.5h8.9v3.9M146 110.5h5.1M151.1 109.2v24.2"/>
<path d="M158.7 116.8h3.9M162.6 104.1h-3.9v29.3M176.5 115.6h-3.8v17.8h-6.3M478.8 108h44.4M478.8 105.4h44.4M491.5 118.1l2.5 2.6h29.2M491.5 113l2.5 2.6h29.2M491.5 115.6l2.5 2.5h29.2M502.9 113h20.3M510.5 109.2h2.6v1.3h10.1M217.2 138.4l-2.6 2.6h-31.7M217.2 135.9l-2.6 2.5h-31.7"/>
<path d="M384.8 138.4h-5.1v16.5M491.5 130.8l2.5 2.6h29.2M491.5 128.3l2.5 2.5h29.2M491.5 123.2l2.5 2.5h29.2M491.5 125.7l2.5 2.6h29.2M491.5 120.7l2.5 2.5h29.2M492.8 138.4l2.5 2.6h27.9M492.8 135.9l2.5 2.5h27.9M492.8 133.4l2.5 2.5h27.9M92.7 146.1l2.5 2.5h20.4M92.7 148.6l2.5 2.5h20.4M92.7 151.1l2.5 2.6h20.4"/>
<path d="M92.7 143.5l2.5 2.6h20.4M217.2 153.7l-2.6 2.5h-31.7M217.2 146.1l-2.6 2.5h-31.7M217.2 148.6l-2.6 2.5h-31.7M217.2 151.1l-2.6 2.6h-31.7M217.2 143.5l-2.6 2.6h-31.7M217.2 141l-2.6 2.5h-31.7M218.4 158.8l-2.5 2.5h-33M218.4 156.2l-2.5 2.6h-33M358.1 149.9h-7.6v10.1h19.1M365.8 149.9h13.9M414 148.6h-15.2v11.4h-8.9"/>
<path d="M492.8 146.1l2.5 2.5h27.9M492.8 148.6l2.5 2.5h27.9M492.8 151.1l2.5 2.6h27.9M492.8 143.5l2.5 2.6h27.9M492.8 141l2.5 2.5h27.9M494 158.8l2.6 2.5h26.6M494 156.2l2.6 2.6h26.6M494 153.7l2.6 2.5h26.6M52.1 166.4h63.5M218.4 163.8l-2.5 2.6h-33M218.4 161.3l-2.5 2.5h-33M218.4 174l-2.5 2.5h-33"/>
<path d="M218.4 171.5l-2.5 2.5h-33M218.4 168.9l-2.5 2.6h-33M218.4 166.4l-2.5 2.5h-33M219.7 176.5l-2.5 2.6h-34.3M219.7 179.1l-2.5 2.5h-34.3M341.6 165.1h28M389.9 165.1h7.6v7.6M397.5 167.6h17.8M494 163.8l2.6 2.6h26.6M494 161.3l2.6 2.5h26.6M494 171.5l2.6 2.5h26.6M494 168.9l2.6 2.6h26.6"/>
<path d="M494 166.4l2.6 2.5h26.6M496.6 176.5h26.6M523.2 179.1h-24.1v8.9h-30.5M182.9 199.4h53.3M219.7 191.8l-2.5 2.5h-34.3M219.7 194.3l-2.5 2.6h-34.3M219.7 189.2l-2.5 2.6h-34.3M219.7 181.6l-2.5 2.6h-34.3M219.7 186.7l-2.5 2.5h-34.3M219.7 184.2l-2.5 2.5h-34.3M513.1 194.3h10.1M523.2 184.2h-20.3v10.1h-30.5"/>
<path d="M523.2 186.7h-19v10.2h-31.8M523.2 181.6h-21.6v10.2h-30.4M523.2 189.2h-17.7v10.2h-33.1M182.9 201.9h53.3M182.9 207h53.3M182.9 209.6h53.3M182.9 212.1h53.3M182.9 204.5h53.3M146 222.3v3.8h7.7v-3.8M148.6 222.3v3.8M149.9 226.1v1.2M151.1 222.3v3.8"/>
<path d="M45.7 257.8h19.1M45.7 255.3h19.1M44.4 273.1h21.6v2.5h5.1M71.1 268h-5.1v2.5h-21.6M104.1 274.3h12.7M107.9 279.4h8.9M107.9 276.9h8.9M137.2 274.3h12.7M137.2 279.4h7.6M137.2 276.9h7.6M492.8 279.4h2.5M494 274.3h-1.2v6.4"/>
<path d="M502.9 279.4h2.6v8.9h12.7v5.1M504.2 274.3v5.1M45.7 288.3h19.1M45.7 290.8h19.1M104.1 281.9h12.7M137.2 281.9h12.7M467.4 294.6v14M475 294.6h17.8v3.9h26.6M482.6 294.6v2.6M516.9 293.4h2.5M529.6 285.8v-2.6h2.5v2.6M538.5 283.2h-3.8v2.6"/>
<path d="M547.4 292.1h-1.3v6.4h-1.3M549.9 295.9v5.1h-5.1M590.5 297.2h3.6M45.7 301h19.1M45.7 303.5h19.1M462.3 301h15.2M482.6 304.8v3.8M487.7 301h2.5M516.9 308.6h2.5M519.4 301h-26.6v7.6h-17.8M544.8 303.5h15.3M544.8 311.2h15.3"/>
<path d="M544.8 313.7h25.4M544.8 316.2h25.4M544.8 308.6h15.3M544.8 306.1h15.3M590.5 317.5h3.6M509.3 321.3h10.1M532.1 339.1v2.5h2.6v-2.5M544.8 321.3h7.6M544.8 326.4h2.6M544.8 323.9h7.6M544.8 328.9h2.6"/>
</g>
<g fill="none" stroke="#0000c2" stroke-width=".26">
<path d="M24.1 21.6h91.5v40.6h-91.5zM134.4 22.2h50.8v39.4h-50.8zM205.5 22.9h67.5v40h-67.5zM283.2 21.6h122.6v41.9h-122.6zM289.3 22.7h.5l.1 .3-.8 1h.8M301.1 23.1v.9M301.1 23.2h.5v.8M421 24.8h95.9v38.7h-95.9zM444.2 36.4l.3-.1 .2 .2M444.7 36.5l.2-.2 .3 .1 .1 .8M444.7 36.5v.7M456.5 36.8v.3"/>
<path d="M61.9 46.8h.4l.1 .8M68.5 46.7l.3 .1M68.5 47.2l.4 .2-.5 .2M68.6 49.6v.8M69.1 49.5h.4M69.2 49.1v1.1l.3 .2M83.9 49.5v1.3M83.9 50.3l.2 .1M84.1 49.5l-.2 .1M85 46.7l-.2 .3v.3l.2 .3M86.9 55.4h.4M87 54.9l.1 1.2"/>
<path d="M90.8 49.9h1M91.4 55.4l-.5 .2 .1 .5 .4 .1M92.4 49.9h1M93 46.9h.4M93.6 46.3h-.6v1.3h.6M95.5 49.6l-.4-.1-.2 .3 .1 .5h.5M99.1 54.9v.2M99.1 55.4v.8M101.8 49.5h.5M101.8 47.9h-.5M101.9 46.8l-.4-.1-.2 .3 .1 .5h.5M101.9 55.4h.4"/>
<path d="M102.3 49.1l-.3 .2v1.1M102.3 56.1l-.4 .1M106.5 46.7h.5M106.7 47.4l.3 .2M107.2 50.2l.2 .2 .4-.1M107.3 49.6h.5v.8M107.8 49.8l-.6 .3M109.9 46.7l.2 .2v.7M110.1 47.5l-.4 .1M110.1 47l-.4 .1M21.6 82.6h527v149.8h-527zM38 86.9l.2 .1v.7"/>
<path d="M491.9 97.8h.5M492.2 98.6h.2M493.2 97.8h-.3l-.2 .2 .5 .3v.3h-.5M504.7 99.9l.2 .5-.2 .3h-.4M505.5 99.9a.53 .53 0 0 1 .6 .6l-.7 .1M506.6 99.8l.6 .9M507.2 99.8l-.6 .9M509.4 98.5l.2 .1M510.1 97.4h-.6l-.1 .6 .2-.2M511.6 98.4l.4 .2M512 97.8l-.4 .2M514.5 98.3l.5 .3"/>
<path d="M515 97.4l-.5 .3M517.2 99.4v1.1l.3 .2M337.6 139v1.3M337.6 139.5l-.3-.1-.3 .3 .2 .5h.4M348.6 139.4h.5M348.8 139v1.1l.3 .2M353.9 139.4h.5M354.1 139l.1 1.2M358 139v.1M358 139.4v.9M408.2 177.4h1M408.2 178.1h1"/>
<path d="M408.7 176.9v1M409.7 178.1h.7M409.7 177.2l.4-.3v1.2M411.9 176.9l-1 1.2M416.4 176.9l.2 .2v.3l-.8 .7h.8M477.6 204.6l.1-.1a.62 .62 0 0 1 .5 .7 .62 .62 0 0 1-.6 .5l-.2-.4zM478.5 207l.2 .1M478.7 206.6v1.3M478.7 207.8l-.2 .1M490.8 205l.2 .3-.6 .1M490.9 205.7l-.1 .1M497.4 207v.9"/>
<path d="M497.4 207.1h.4l.1 .8M498.7 205v1.2M498.7 205.7l.2 .1M498.9 205h-.2M27.9 243.8h52.1v68.6h-52.1zM37.1 247.1l-.4 .3M53.4 247.2h.4M53.4 247.5l.5 .2-.4 .3M87.6 247.7h77.5v64.7h-77.5zM453.4 250.2h124.4v102.9h-124.4zM473.7 254l.7 .8M474.4 254l-.7 .8"/>
<circle cx="411.1" cy="177" r=".18"/>
<circle cx="411.7" cy="178" r=".18"/>
</g>
<path d="M543.8 308.2h.7M520.9 320.9h.8" fill="none" stroke="#a90000" stroke-width=".26"/>
<g fill="#009600" stroke="#009600" stroke-width=".26">
<circle cx="534.7" cy="341.6" r=".46"/>
<circle cx="529.6" cy="283.2" r=".46"/>
<circle cx="467.4" cy="301" r=".46"/>
<circle cx="492.8" cy="279.4" r=".46"/>
<circle cx="504.2" cy="279.4" r=".46"/>
<circle cx="482.6" cy="294.6" r=".46"/>
<circle cx="482.6" cy="308.6" r=".46"/>
<circle cx="518.2" cy="293.4" r=".46"/>
<circle cx="172.7" cy="115.6" r=".46"/>
<circle cx="241.3" cy="39.4" r=".46"/>
<circle cx="251.5" cy="39.4" r=".46"/>
<circle cx="254" cy="39.4" r=".46"/>
<circle cx="259.1" cy="39.4" r=".46"/>
<circle cx="217.2" cy="39.4" r=".46"/>
<circle cx="209.5" cy="39.4" r=".46"/>
<circle cx="228.6" cy="54.6" r=".46"/>
<circle cx="162.6" cy="50.8" r=".46"/>
<circle cx="175.3" cy="40.6" r=".46"/>
<circle cx="149.9" cy="40.6" r=".46"/>
<circle cx="143.5" cy="40.6" r=".46"/>
<circle cx="121.9" cy="111.8" r=".46"/>
<circle cx="107.9" cy="113" r=".46"/>
<circle cx="94" cy="114.3" r=".46"/>
<circle cx="151.1" cy="110.5" r=".46"/>
<circle cx="134.6" cy="113" r=".46"/>
<circle cx="158.7" cy="116.8" r=".46"/>
<circle cx="158.7" cy="104.1" r=".46"/>
<circle cx="335.3" cy="47" r=".46"/>
<circle cx="335.3" cy="54.6" r=".46"/>
<circle cx="322.6" cy="36.8" r=".46"/>
<circle cx="345.4" cy="47" r=".46"/>
<circle cx="372.1" cy="44.5" r=".46"/>
<circle cx="403.9" cy="148.6" r=".46"/>
<circle cx="379.7" cy="138.4" r=".46"/>
<circle cx="397.5" cy="167.6" r=".46"/>
<circle cx="379.7" cy="149.9" r=".46"/>
<circle cx="151.1" cy="226.1" r=".46"/>
<circle cx="149.9" cy="226.1" r=".46"/>
<circle cx="148.6" cy="226.1" r=".46"/>
<circle cx="149.9" cy="274.3" r=".46"/>
<circle cx="104.1" cy="274.3" r=".46"/>
<circle cx="104.1" cy="281.9" r=".46"/>
<circle cx="149.9" cy="281.9" r=".46"/>
</g>
<use href="#words"/>
</svg>
